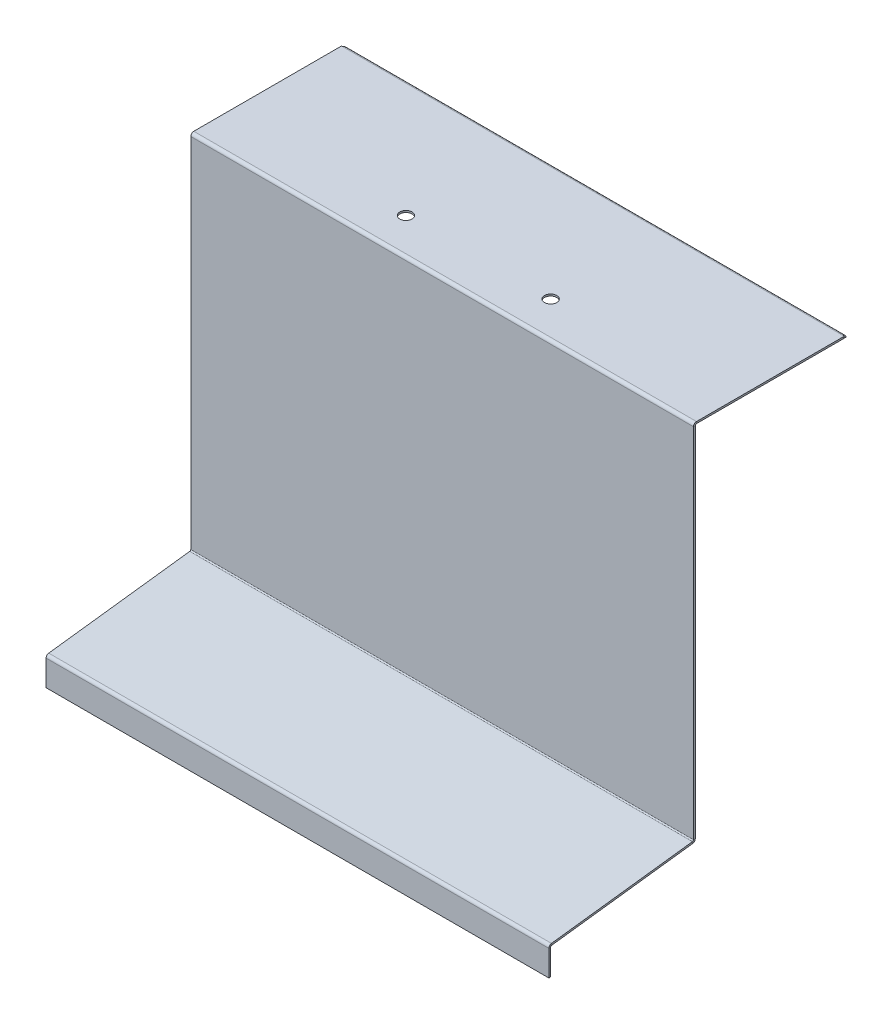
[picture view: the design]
ISO-10303-21;
HEADER;
FILE_DESCRIPTION(('STEP AP214'),'2;1');
FILE_NAME('part.step','',(''),(''),'','','');
FILE_SCHEMA(('AUTOMOTIVE_DESIGN { 1 0 10303 214 1 1 1 1 }'));
ENDSEC;
DATA;
#1=APPLICATION_CONTEXT('core data for automotive mechanical design processes');
#2=APPLICATION_PROTOCOL_DEFINITION('international standard','automotive_design',2000,#1);
#3=PRODUCT_CONTEXT('',#1,'mechanical');
#4=PRODUCT('Part','Part','',(#3));
#5=PRODUCT_RELATED_PRODUCT_CATEGORY('part','',(#4));
#6=PRODUCT_DEFINITION_FORMATION('','',#4);
#7=PRODUCT_DEFINITION_CONTEXT('part definition',#1,'design');
#8=PRODUCT_DEFINITION('design','',#6,#7);
#9=PRODUCT_DEFINITION_SHAPE('','',#8);
#10=(LENGTH_UNIT() NAMED_UNIT(*) SI_UNIT(.MILLI.,.METRE.));
#11=(NAMED_UNIT(*) PLANE_ANGLE_UNIT() SI_UNIT($,.RADIAN.));
#12=(NAMED_UNIT(*) SI_UNIT($,.STERADIAN.) SOLID_ANGLE_UNIT());
#13=UNCERTAINTY_MEASURE_WITH_UNIT(LENGTH_MEASURE(1.E-05),#10,'distance_accuracy_value','');
#14=(GEOMETRIC_REPRESENTATION_CONTEXT(3) GLOBAL_UNCERTAINTY_ASSIGNED_CONTEXT((#13)) GLOBAL_UNIT_ASSIGNED_CONTEXT((#10,
#11,#12)) REPRESENTATION_CONTEXT('',''));
#15=CARTESIAN_POINT('',(0.,0.,0.));
#16=DIRECTION('',(0.,0.,1.));
#17=DIRECTION('',(1.,0.,0.));
#18=AXIS2_PLACEMENT_3D('',#15,#16,#17);
#19=CARTESIAN_POINT('',(0.,338.5,-125.));
#20=DIRECTION('',(0.,-1.,0.));
#21=DIRECTION('',(0.,0.,-1.));
#22=AXIS2_PLACEMENT_3D('',#19,#20,#21);
#23=PLANE('',#22);
#24=CARTESIAN_POINT('',(148.5,338.5,-30.));
#25=DIRECTION('',(0.,-1.,0.));
#26=DIRECTION('',(0.,0.,-1.));
#27=AXIS2_PLACEMENT_3D('',#24,#25,#26);
#28=CIRCLE('',#27,5.09999999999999);
#29=CARTESIAN_POINT('',(148.5,338.5,-35.1));
#30=VERTEX_POINT('',#29);
#31=EDGE_CURVE('E643',#30,#30,#28,.T.);
#32=ORIENTED_EDGE('',*,*,#31,.F.);
#33=EDGE_LOOP('',(#32));
#34=FACE_BOUND('',#33,.T.);
#35=CARTESIAN_POINT('',(268.5,338.5,-30.));
#36=DIRECTION('',(0.,-1.,0.));
#37=DIRECTION('',(0.,0.,-1.));
#38=AXIS2_PLACEMENT_3D('',#35,#36,#37);
#39=CIRCLE('',#38,5.09999999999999);
#40=CARTESIAN_POINT('',(268.5,338.5,-35.1));
#41=VERTEX_POINT('',#40);
#42=EDGE_CURVE('E637',#41,#41,#39,.T.);
#43=ORIENTED_EDGE('',*,*,#42,.F.);
#44=EDGE_LOOP('',(#43));
#45=FACE_BOUND('',#44,.T.);
#46=DIRECTION('',(1.,0.,0.));
#47=VECTOR('',#46,1.);
#48=CARTESIAN_POINT('',(0.,338.5,-125.));
#49=LINE('',#48,#47);
#50=CARTESIAN_POINT('',(1.07071068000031,338.5,-124.9999999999));
#51=VERTEX_POINT('',#50);
#52=CARTESIAN_POINT('',(0.,338.5,-125.));
#53=VERTEX_POINT('',#52);
#54=EDGE_CURVE('E73',#51,#53,#49,.F.);
#55=ORIENTED_EDGE('',*,*,#54,.F.);
#56=DIRECTION('',(1.,0.,0.));
#57=VECTOR('',#56,1.);
#58=CARTESIAN_POINT('',(0.,338.5,-124.999999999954));
#59=LINE('',#58,#57);
#60=CARTESIAN_POINT('',(415.9292893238,338.5,-124.9999999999));
#61=VERTEX_POINT('',#60);
#62=EDGE_CURVE('E57',#51,#61,#59,.T.);
#63=ORIENTED_EDGE('',*,*,#62,.T.);
#64=CARTESIAN_POINT('',(417.,338.5,-125.));
#65=VERTEX_POINT('',#64);
#66=EDGE_CURVE('E409',#65,#61,#49,.F.);
#67=ORIENTED_EDGE('',*,*,#66,.F.);
#68=DIRECTION('',(0.,0.,-1.));
#69=VECTOR('',#68,1.);
#70=CARTESIAN_POINT('',(417.,338.5,-125.));
#71=LINE('',#70,#69);
#72=CARTESIAN_POINT('',(417.,338.5,-2.5));
#73=VERTEX_POINT('',#72);
#74=EDGE_CURVE('E402',#73,#65,#71,.T.);
#75=ORIENTED_EDGE('',*,*,#74,.F.);
#76=DIRECTION('',(1.,0.,0.));
#77=VECTOR('',#76,1.);
#78=CARTESIAN_POINT('',(0.,338.5,-2.5));
#79=LINE('',#78,#77);
#80=CARTESIAN_POINT('',(0.,338.5,-2.5));
#81=VERTEX_POINT('',#80);
#82=EDGE_CURVE('E376',#81,#73,#79,.T.);
#83=ORIENTED_EDGE('',*,*,#82,.F.);
#84=DIRECTION('',(0.,0.,-1.));
#85=VECTOR('',#84,1.);
#86=CARTESIAN_POINT('',(0.,338.5,-125.));
#87=LINE('',#86,#85);
#88=EDGE_CURVE('E407',#53,#81,#87,.F.);
#89=ORIENTED_EDGE('',*,*,#88,.F.);
#90=EDGE_LOOP('',(#55,#63,#67,#75,#83,#89));
#91=FACE_BOUND('',#90,.T.);
#92=ADVANCED_FACE('F49',(#34,#45,#91),#23,.T.);
#93=CARTESIAN_POINT('',(0.,340.,-125.));
#94=DIRECTION('',(0.,-1.,0.));
#95=DIRECTION('',(0.,0.,-1.));
#96=AXIS2_PLACEMENT_3D('',#93,#94,#95);
#97=PLANE('',#96);
#98=CARTESIAN_POINT('',(148.5,340.,-30.));
#99=DIRECTION('',(0.,1.,0.));
#100=DIRECTION('',(0.,0.,1.));
#101=AXIS2_PLACEMENT_3D('',#98,#99,#100);
#102=CIRCLE('',#101,5.09999999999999);
#103=CARTESIAN_POINT('',(148.5,340.,-24.9));
#104=VERTEX_POINT('',#103);
#105=EDGE_CURVE('E646',#104,#104,#102,.T.);
#106=ORIENTED_EDGE('',*,*,#105,.F.);
#107=EDGE_LOOP('',(#106));
#108=FACE_BOUND('',#107,.T.);
#109=CARTESIAN_POINT('',(268.5,340.,-30.));
#110=DIRECTION('',(0.,1.,0.));
#111=DIRECTION('',(0.,0.,1.));
#112=AXIS2_PLACEMENT_3D('',#109,#110,#111);
#113=CIRCLE('',#112,5.09999999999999);
#114=CARTESIAN_POINT('',(268.5,340.,-24.9));
#115=VERTEX_POINT('',#114);
#116=EDGE_CURVE('E640',#115,#115,#113,.T.);
#117=ORIENTED_EDGE('',*,*,#116,.F.);
#118=EDGE_LOOP('',(#117));
#119=FACE_BOUND('',#118,.T.);
#120=DIRECTION('',(1.,0.,0.));
#121=VECTOR('',#120,1.);
#122=CARTESIAN_POINT('',(0.,340.,-124.999999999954));
#123=LINE('',#122,#121);
#124=CARTESIAN_POINT('',(1.07071068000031,340.,-124.9999999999));
#125=VERTEX_POINT('',#124);
#126=CARTESIAN_POINT('',(415.9292893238,340.,-125.));
#127=VERTEX_POINT('',#126);
#128=EDGE_CURVE('E457',#125,#127,#123,.T.);
#129=ORIENTED_EDGE('',*,*,#128,.F.);
#130=DIRECTION('',(-1.,0.,0.));
#131=VECTOR('',#130,1.);
#132=CARTESIAN_POINT('',(0.,340.,-125.));
#133=LINE('',#132,#131);
#134=CARTESIAN_POINT('',(0.,340.,-125.));
#135=VERTEX_POINT('',#134);
#136=EDGE_CURVE('E385',#125,#135,#133,.T.);
#137=ORIENTED_EDGE('',*,*,#136,.T.);
#138=DIRECTION('',(0.,0.,1.));
#139=VECTOR('',#138,1.);
#140=CARTESIAN_POINT('',(0.,340.,0.));
#141=LINE('',#140,#139);
#142=CARTESIAN_POINT('',(0.,340.,-2.49999999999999));
#143=VERTEX_POINT('',#142);
#144=EDGE_CURVE('E397',#135,#143,#141,.T.);
#145=ORIENTED_EDGE('',*,*,#144,.T.);
#146=DIRECTION('',(1.,0.,0.));
#147=VECTOR('',#146,1.);
#148=CARTESIAN_POINT('',(0.,340.,-2.5));
#149=LINE('',#148,#147);
#150=CARTESIAN_POINT('',(417.,340.,-2.5));
#151=VERTEX_POINT('',#150);
#152=EDGE_CURVE('E395',#143,#151,#149,.T.);
#153=ORIENTED_EDGE('',*,*,#152,.T.);
#154=DIRECTION('',(0.,0.,-1.));
#155=VECTOR('',#154,1.);
#156=CARTESIAN_POINT('',(417.,340.,0.));
#157=LINE('',#156,#155);
#158=CARTESIAN_POINT('',(417.,340.,-125.));
#159=VERTEX_POINT('',#158);
#160=EDGE_CURVE('E392',#151,#159,#157,.T.);
#161=ORIENTED_EDGE('',*,*,#160,.T.);
#162=EDGE_CURVE('E387',#159,#127,#133,.T.);
#163=ORIENTED_EDGE('',*,*,#162,.T.);
#164=EDGE_LOOP('',(#129,#137,#145,#153,#161,#163));
#165=FACE_BOUND('',#164,.T.);
#166=ADVANCED_FACE('F652',(#108,#119,#165),#97,.F.);
#167=CARTESIAN_POINT('',(417.,40.,0.));
#168=DIRECTION('',(-1.,0.,0.));
#169=DIRECTION('',(0.,-0.124034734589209,0.992277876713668));
#170=AXIS2_PLACEMENT_3D('',#167,#168,#169);
#171=PLANE('',#170);
#172=DIRECTION('',(0.,0.992277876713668,0.124034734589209));
#173=VECTOR('',#172,1.);
#174=CARTESIAN_POINT('',(417.,25.2737391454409,117.810086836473));
#175=LINE('',#174,#173);
#176=CARTESIAN_POINT('',(417.,23.7853223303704,117.624034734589));
#177=VERTEX_POINT('',#176);
#178=CARTESIAN_POINT('',(417.,25.2737391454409,117.810086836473));
#179=VERTEX_POINT('',#178);
#180=EDGE_CURVE('E454',#177,#179,#175,.T.);
#181=ORIENTED_EDGE('',*,*,#180,.F.);
#182=DIRECTION('',(0.,-0.124034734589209,0.992277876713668));
#183=VECTOR('',#182,1.);
#184=CARTESIAN_POINT('',(417.,38.5115831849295,-0.186052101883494));
#185=LINE('',#184,#183);
#186=CARTESIAN_POINT('',(417.,38.4020875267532,0.689913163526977));
#187=VERTEX_POINT('',#186);
#188=EDGE_CURVE('E430',#187,#177,#185,.T.);
#189=ORIENTED_EDGE('',*,*,#188,.F.);
#190=DIRECTION('',(-1.11022302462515E-13,0.992277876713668,0.124034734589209));
#191=VECTOR('',#190,1.);
#192=CARTESIAN_POINT('',(417.,39.8905043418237,0.875965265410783));
#193=LINE('',#192,#191);
#194=CARTESIAN_POINT('',(417.,39.8905043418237,0.87596526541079));
#195=VERTEX_POINT('',#194);
#196=EDGE_CURVE('E436',#187,#195,#193,.T.);
#197=ORIENTED_EDGE('',*,*,#196,.T.);
#198=DIRECTION('',(0.,-0.124034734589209,0.992277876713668));
#199=VECTOR('',#198,1.);
#200=CARTESIAN_POINT('',(417.,40.,0.));
#201=LINE('',#200,#199);
#202=EDGE_CURVE('E429',#195,#179,#201,.T.);
#203=ORIENTED_EDGE('',*,*,#202,.T.);
#204=EDGE_LOOP('',(#181,#189,#197,#203));
#205=FACE_BOUND('',#204,.T.);
#206=ADVANCED_FACE('F655',(#205),#171,.F.);
#207=CARTESIAN_POINT('',(0.,40.,3.33066907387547E-13));
#208=DIRECTION('',(1.,0.,0.));
#209=DIRECTION('',(0.,0.124034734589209,-0.992277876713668));
#210=AXIS2_PLACEMENT_3D('',#207,#208,#209);
#211=PLANE('',#210);
#212=DIRECTION('',(0.,0.992277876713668,0.124034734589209));
#213=VECTOR('',#212,1.);
#214=CARTESIAN_POINT('',(0.,39.8905043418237,0.87596526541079));
#215=LINE('',#214,#213);
#216=CARTESIAN_POINT('',(0.,38.4020875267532,0.689913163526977));
#217=VERTEX_POINT('',#216);
#218=CARTESIAN_POINT('',(0.,39.8905043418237,0.875965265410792));
#219=VERTEX_POINT('',#218);
#220=EDGE_CURVE('E442',#217,#219,#215,.T.);
#221=ORIENTED_EDGE('',*,*,#220,.F.);
#222=DIRECTION('',(0.,-0.124034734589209,0.992277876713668));
#223=VECTOR('',#222,1.);
#224=CARTESIAN_POINT('',(0.,38.5115831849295,-0.18605210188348));
#225=LINE('',#224,#223);
#226=CARTESIAN_POINT('',(0.,23.7853223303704,117.624034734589));
#227=VERTEX_POINT('',#226);
#228=EDGE_CURVE('E339',#227,#217,#225,.F.);
#229=ORIENTED_EDGE('',*,*,#228,.F.);
#230=DIRECTION('',(0.,0.992277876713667,0.12403473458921));
#231=VECTOR('',#230,1.);
#232=CARTESIAN_POINT('',(0.,25.2737391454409,117.810086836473));
#233=LINE('',#232,#231);
#234=CARTESIAN_POINT('',(0.,25.2737391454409,117.810086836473));
#235=VERTEX_POINT('',#234);
#236=EDGE_CURVE('E448',#227,#235,#233,.T.);
#237=ORIENTED_EDGE('',*,*,#236,.T.);
#238=DIRECTION('',(0.,0.124034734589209,-0.992277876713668));
#239=VECTOR('',#238,1.);
#240=CARTESIAN_POINT('',(0.,40.,3.33066907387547E-13));
#241=LINE('',#240,#239);
#242=EDGE_CURVE('E426',#235,#219,#241,.T.);
#243=ORIENTED_EDGE('',*,*,#242,.T.);
#244=EDGE_LOOP('',(#221,#229,#237,#243));
#245=FACE_BOUND('',#244,.T.);
#246=ADVANCED_FACE('F903',(#245),#211,.F.);
#247=CARTESIAN_POINT('',(-126.491106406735,40.,3.33066907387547E-13));
#248=DIRECTION('',(0.,0.992277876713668,0.124034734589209));
#249=DIRECTION('',(0.,-0.124034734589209,0.992277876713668));
#250=AXIS2_PLACEMENT_3D('',#247,#248,#249);
#251=PLANE('',#250);
#252=ORIENTED_EDGE('',*,*,#202,.F.);
#253=DIRECTION('',(-1.,0.,0.));
#254=VECTOR('',#253,1.);
#255=CARTESIAN_POINT('',(-126.491106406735,39.8905043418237,0.875965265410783));
#256=LINE('',#255,#254);
#257=EDGE_CURVE('E432',#195,#219,#256,.T.);
#258=ORIENTED_EDGE('',*,*,#257,.T.);
#259=ORIENTED_EDGE('',*,*,#242,.F.);
#260=DIRECTION('',(1.,0.,0.));
#261=VECTOR('',#260,1.);
#262=CARTESIAN_POINT('',(-126.491106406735,25.2737391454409,117.810086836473));
#263=LINE('',#262,#261);
#264=EDGE_CURVE('E445',#235,#179,#263,.T.);
#265=ORIENTED_EDGE('',*,*,#264,.T.);
#266=EDGE_LOOP('',(#252,#258,#259,#265));
#267=FACE_BOUND('',#266,.T.);
#268=ADVANCED_FACE('F897',(#267),#251,.T.);
#269=CARTESIAN_POINT('',(-126.491106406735,38.5115831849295,-0.18605210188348));
#270=DIRECTION('',(0.,0.992277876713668,0.124034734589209));
#271=DIRECTION('',(0.,-0.124034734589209,0.992277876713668));
#272=AXIS2_PLACEMENT_3D('',#269,#270,#271);
#273=PLANE('',#272);
#274=ORIENTED_EDGE('',*,*,#188,.T.);
#275=DIRECTION('',(1.,0.,0.));
#276=VECTOR('',#275,1.);
#277=CARTESIAN_POINT('',(-126.491106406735,23.7853223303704,117.624034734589));
#278=LINE('',#277,#276);
#279=EDGE_CURVE('E451',#227,#177,#278,.T.);
#280=ORIENTED_EDGE('',*,*,#279,.F.);
#281=ORIENTED_EDGE('',*,*,#228,.T.);
#282=DIRECTION('',(-1.,0.,0.));
#283=VECTOR('',#282,1.);
#284=CARTESIAN_POINT('',(-126.491106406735,38.4020875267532,0.689913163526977));
#285=LINE('',#284,#283);
#286=EDGE_CURVE('E439',#187,#217,#285,.T.);
#287=ORIENTED_EDGE('',*,*,#286,.F.);
#288=EDGE_LOOP('',(#274,#280,#281,#287));
#289=FACE_BOUND('',#288,.T.);
#290=ADVANCED_FACE('F893',(#289),#273,.F.);
#291=CARTESIAN_POINT('',(0.,340.,-125.));
#292=DIRECTION('',(0.,0.,1.));
#293=DIRECTION('',(-1.,0.,0.));
#294=AXIS2_PLACEMENT_3D('',#291,#292,#293);
#295=PLANE('',#294);
#296=DIRECTION('',(0.,1.,0.));
#297=VECTOR('',#296,1.);
#298=CARTESIAN_POINT('',(1.07071068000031,338.5,-124.9999999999));
#299=LINE('',#298,#297);
#300=EDGE_CURVE('E12',#51,#125,#299,.T.);
#301=ORIENTED_EDGE('',*,*,#300,.F.);
#302=ORIENTED_EDGE('',*,*,#54,.T.);
#303=DIRECTION('',(0.,1.,0.));
#304=VECTOR('',#303,1.);
#305=CARTESIAN_POINT('',(0.,340.,-125.));
#306=LINE('',#305,#304);
#307=EDGE_CURVE('E411',#53,#135,#306,.T.);
#308=ORIENTED_EDGE('',*,*,#307,.T.);
#309=ORIENTED_EDGE('',*,*,#136,.F.);
#310=EDGE_LOOP('',(#301,#302,#308,#309));
#311=FACE_BOUND('',#310,.T.);
#312=ADVANCED_FACE('F668',(#311),#295,.F.);
#313=ORIENTED_EDGE('',*,*,#66,.T.);
#314=DIRECTION('',(0.,1.,0.));
#315=VECTOR('',#314,1.);
#316=CARTESIAN_POINT('',(415.9292893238,338.5,-124.9999999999));
#317=LINE('',#316,#315);
#318=EDGE_CURVE('E460',#61,#127,#317,.T.);
#319=ORIENTED_EDGE('',*,*,#318,.T.);
#320=ORIENTED_EDGE('',*,*,#162,.F.);
#321=DIRECTION('',(0.,1.,0.));
#322=VECTOR('',#321,1.);
#323=CARTESIAN_POINT('',(417.,340.,-125.));
#324=LINE('',#323,#322);
#325=EDGE_CURVE('E400',#65,#159,#324,.T.);
#326=ORIENTED_EDGE('',*,*,#325,.F.);
#327=EDGE_LOOP('',(#313,#319,#320,#326));
#328=FACE_BOUND('',#327,.T.);
#329=ADVANCED_FACE('F675',(#328),#295,.F.);
#330=CARTESIAN_POINT('',(0.,340.,0.));
#331=DIRECTION('',(1.,0.,0.));
#332=DIRECTION('',(0.,0.,1.));
#333=AXIS2_PLACEMENT_3D('',#330,#331,#332);
#334=PLANE('',#333);
#335=ORIENTED_EDGE('',*,*,#307,.F.);
#336=ORIENTED_EDGE('',*,*,#88,.T.);
#337=DIRECTION('',(0.,1.,0.));
#338=VECTOR('',#337,1.);
#339=CARTESIAN_POINT('',(0.,340.,-2.5));
#340=LINE('',#339,#338);
#341=EDGE_CURVE('E405',#81,#143,#340,.T.);
#342=ORIENTED_EDGE('',*,*,#341,.T.);
#343=ORIENTED_EDGE('',*,*,#144,.F.);
#344=EDGE_LOOP('',(#335,#336,#342,#343));
#345=FACE_BOUND('',#344,.T.);
#346=ADVANCED_FACE('F711',(#345),#334,.F.);
#347=CARTESIAN_POINT('',(417.,340.,0.));
#348=DIRECTION('',(-1.,0.,0.));
#349=DIRECTION('',(0.,0.,-1.));
#350=AXIS2_PLACEMENT_3D('',#347,#348,#349);
#351=PLANE('',#350);
#352=DIRECTION('',(0.,1.,0.));
#353=VECTOR('',#352,1.);
#354=CARTESIAN_POINT('',(417.,340.,-2.5));
#355=LINE('',#354,#353);
#356=EDGE_CURVE('E367',#73,#151,#355,.T.);
#357=ORIENTED_EDGE('',*,*,#356,.F.);
#358=ORIENTED_EDGE('',*,*,#74,.T.);
#359=ORIENTED_EDGE('',*,*,#325,.T.);
#360=ORIENTED_EDGE('',*,*,#160,.F.);
#361=EDGE_LOOP('',(#357,#358,#359,#360));
#362=FACE_BOUND('',#361,.T.);
#363=ADVANCED_FACE('F679',(#362),#351,.F.);
#364=CARTESIAN_POINT('',(0.,337.5,-2.5));
#365=DIRECTION('',(-1.,0.,0.));
#366=DIRECTION('',(0.,0.,1.));
#367=AXIS2_PLACEMENT_3D('',#364,#365,#366);
#368=PLANE('',#367);
#369=ORIENTED_EDGE('',*,*,#341,.F.);
#370=CARTESIAN_POINT('',(0.,337.5,-2.5));
#371=DIRECTION('',(-1.,0.,0.));
#372=DIRECTION('',(0.,0.,1.));
#373=AXIS2_PLACEMENT_3D('',#370,#371,#372);
#374=CIRCLE('',#373,1.);
#375=CARTESIAN_POINT('',(0.,337.5,-1.5));
#376=VERTEX_POINT('',#375);
#377=EDGE_CURVE('E382',#81,#376,#374,.F.);
#378=ORIENTED_EDGE('',*,*,#377,.T.);
#379=DIRECTION('',(0.,0.,1.));
#380=VECTOR('',#379,1.);
#381=CARTESIAN_POINT('',(0.,337.5,0.));
#382=LINE('',#381,#380);
#383=CARTESIAN_POINT('',(0.,337.5,0.));
#384=VERTEX_POINT('',#383);
#385=EDGE_CURVE('E379',#376,#384,#382,.T.);
#386=ORIENTED_EDGE('',*,*,#385,.T.);
#387=CARTESIAN_POINT('',(0.,337.5,-2.5));
#388=DIRECTION('',(1.,0.,0.));
#389=DIRECTION('',(0.,0.,-1.));
#390=AXIS2_PLACEMENT_3D('',#387,#388,#389);
#391=CIRCLE('',#390,2.5);
#392=EDGE_CURVE('E364',#143,#384,#391,.T.);
#393=ORIENTED_EDGE('',*,*,#392,.F.);
#394=EDGE_LOOP('',(#369,#378,#386,#393));
#395=FACE_BOUND('',#394,.T.);
#396=ADVANCED_FACE('F689',(#395),#368,.T.);
#397=CARTESIAN_POINT('',(625.511758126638,337.5,-2.5));
#398=DIRECTION('',(-1.,0.,0.));
#399=DIRECTION('',(0.,0.,1.));
#400=AXIS2_PLACEMENT_3D('',#397,#398,#399);
#401=CYLINDRICAL_SURFACE('',#400,1.);
#402=ORIENTED_EDGE('',*,*,#377,.F.);
#403=ORIENTED_EDGE('',*,*,#82,.T.);
#404=CARTESIAN_POINT('',(417.,337.5,-2.5));
#405=DIRECTION('',(-1.,0.,0.));
#406=DIRECTION('',(0.,0.,1.));
#407=AXIS2_PLACEMENT_3D('',#404,#405,#406);
#408=CIRCLE('',#407,1.);
#409=CARTESIAN_POINT('',(417.,337.5,-1.5));
#410=VERTEX_POINT('',#409);
#411=EDGE_CURVE('E370',#410,#73,#408,.T.);
#412=ORIENTED_EDGE('',*,*,#411,.F.);
#413=DIRECTION('',(-1.,0.,0.));
#414=VECTOR('',#413,1.);
#415=CARTESIAN_POINT('',(0.,337.5,-1.5));
#416=LINE('',#415,#414);
#417=EDGE_CURVE('E373',#410,#376,#416,.T.);
#418=ORIENTED_EDGE('',*,*,#417,.T.);
#419=EDGE_LOOP('',(#402,#403,#412,#418));
#420=FACE_BOUND('',#419,.T.);
#421=ADVANCED_FACE('F709',(#420),#401,.F.);
#422=CARTESIAN_POINT('',(417.,337.5,-2.5));
#423=DIRECTION('',(1.,0.,0.));
#424=DIRECTION('',(0.,0.,-1.));
#425=AXIS2_PLACEMENT_3D('',#422,#423,#424);
#426=PLANE('',#425);
#427=DIRECTION('',(0.,0.,1.));
#428=VECTOR('',#427,1.);
#429=CARTESIAN_POINT('',(417.,337.5,0.));
#430=LINE('',#429,#428);
#431=CARTESIAN_POINT('',(417.,337.5,0.));
#432=VERTEX_POINT('',#431);
#433=EDGE_CURVE('E346',#410,#432,#430,.T.);
#434=ORIENTED_EDGE('',*,*,#433,.F.);
#435=ORIENTED_EDGE('',*,*,#411,.T.);
#436=ORIENTED_EDGE('',*,*,#356,.T.);
#437=CARTESIAN_POINT('',(417.,337.5,-2.5));
#438=DIRECTION('',(-1.,0.,0.));
#439=DIRECTION('',(0.,0.,1.));
#440=AXIS2_PLACEMENT_3D('',#437,#438,#439);
#441=CIRCLE('',#440,2.5);
#442=EDGE_CURVE('E361',#432,#151,#441,.T.);
#443=ORIENTED_EDGE('',*,*,#442,.F.);
#444=EDGE_LOOP('',(#434,#435,#436,#443));
#445=FACE_BOUND('',#444,.T.);
#446=ADVANCED_FACE('F706',(#445),#426,.T.);
#447=CARTESIAN_POINT('',(625.511758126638,337.5,-2.5));
#448=DIRECTION('',(-1.,0.,0.));
#449=DIRECTION('',(0.,0.,1.));
#450=AXIS2_PLACEMENT_3D('',#447,#448,#449);
#451=CYLINDRICAL_SURFACE('',#450,2.5);
#452=ORIENTED_EDGE('',*,*,#392,.T.);
#453=DIRECTION('',(-1.,0.,0.));
#454=VECTOR('',#453,1.);
#455=CARTESIAN_POINT('',(0.,337.5,0.));
#456=LINE('',#455,#454);
#457=EDGE_CURVE('E356',#432,#384,#456,.T.);
#458=ORIENTED_EDGE('',*,*,#457,.F.);
#459=ORIENTED_EDGE('',*,*,#442,.T.);
#460=ORIENTED_EDGE('',*,*,#152,.F.);
#461=EDGE_LOOP('',(#452,#458,#459,#460));
#462=FACE_BOUND('',#461,.T.);
#463=ADVANCED_FACE('F684',(#462),#451,.T.);
#464=CARTESIAN_POINT('',(0.,340.,0.));
#465=DIRECTION('',(0.,0.,-1.));
#466=DIRECTION('',(-1.,0.,0.));
#467=AXIS2_PLACEMENT_3D('',#464,#465,#466);
#468=PLANE('',#467);
#469=DIRECTION('',(0.,-1.,0.));
#470=VECTOR('',#469,1.);
#471=CARTESIAN_POINT('',(417.,340.,0.));
#472=LINE('',#471,#470);
#473=CARTESIAN_POINT('',(417.,40.8827822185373,0.));
#474=VERTEX_POINT('',#473);
#475=EDGE_CURVE('E344',#432,#474,#472,.T.);
#476=ORIENTED_EDGE('',*,*,#475,.F.);
#477=ORIENTED_EDGE('',*,*,#457,.T.);
#478=DIRECTION('',(0.,-1.,0.));
#479=VECTOR('',#478,1.);
#480=CARTESIAN_POINT('',(0.,340.,0.));
#481=LINE('',#480,#479);
#482=CARTESIAN_POINT('',(0.,40.8827822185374,0.));
#483=VERTEX_POINT('',#482);
#484=EDGE_CURVE('E354',#384,#483,#481,.T.);
#485=ORIENTED_EDGE('',*,*,#484,.T.);
#486=DIRECTION('',(1.,0.,0.));
#487=VECTOR('',#486,1.);
#488=CARTESIAN_POINT('',(0.,40.8827822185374,0.));
#489=LINE('',#488,#487);
#490=EDGE_CURVE('E351',#483,#474,#489,.T.);
#491=ORIENTED_EDGE('',*,*,#490,.T.);
#492=EDGE_LOOP('',(#476,#477,#485,#491));
#493=FACE_BOUND('',#492,.T.);
#494=ADVANCED_FACE('F698',(#493),#468,.F.);
#495=CARTESIAN_POINT('',(417.,340.,0.));
#496=DIRECTION('',(1.,0.,0.));
#497=DIRECTION('',(0.,-1.,0.));
#498=AXIS2_PLACEMENT_3D('',#495,#496,#497);
#499=PLANE('',#498);
#500=DIRECTION('',(0.,0.,1.));
#501=VECTOR('',#500,1.);
#502=CARTESIAN_POINT('',(417.,40.8827822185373,0.));
#503=LINE('',#502,#501);
#504=CARTESIAN_POINT('',(417.,40.8827822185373,-1.5));
#505=VERTEX_POINT('',#504);
#506=EDGE_CURVE('E417',#505,#474,#503,.T.);
#507=ORIENTED_EDGE('',*,*,#506,.F.);
#508=DIRECTION('',(0.,1.,0.));
#509=VECTOR('',#508,1.);
#510=CARTESIAN_POINT('',(417.,340.,-1.5));
#511=LINE('',#510,#509);
#512=EDGE_CURVE('E342',#410,#505,#511,.F.);
#513=ORIENTED_EDGE('',*,*,#512,.F.);
#514=ORIENTED_EDGE('',*,*,#433,.T.);
#515=ORIENTED_EDGE('',*,*,#475,.T.);
#516=EDGE_LOOP('',(#507,#513,#514,#515));
#517=FACE_BOUND('',#516,.T.);
#518=ADVANCED_FACE('F702',(#517),#499,.T.);
#519=CARTESIAN_POINT('',(0.,340.,-1.5));
#520=DIRECTION('',(0.,0.,-1.));
#521=DIRECTION('',(-1.,0.,0.));
#522=AXIS2_PLACEMENT_3D('',#519,#520,#521);
#523=PLANE('',#522);
#524=ORIENTED_EDGE('',*,*,#512,.T.);
#525=DIRECTION('',(1.,0.,0.));
#526=VECTOR('',#525,1.);
#527=CARTESIAN_POINT('',(0.,40.8827822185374,-1.5));
#528=LINE('',#527,#526);
#529=CARTESIAN_POINT('',(0.,40.8827822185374,-1.5));
#530=VERTEX_POINT('',#529);
#531=EDGE_CURVE('E331',#530,#505,#528,.T.);
#532=ORIENTED_EDGE('',*,*,#531,.F.);
#533=DIRECTION('',(0.,1.,0.));
#534=VECTOR('',#533,1.);
#535=CARTESIAN_POINT('',(0.,340.,-1.5));
#536=LINE('',#535,#534);
#537=EDGE_CURVE('E340',#376,#530,#536,.F.);
#538=ORIENTED_EDGE('',*,*,#537,.F.);
#539=ORIENTED_EDGE('',*,*,#417,.F.);
#540=EDGE_LOOP('',(#524,#532,#538,#539));
#541=FACE_BOUND('',#540,.T.);
#542=ADVANCED_FACE('F935',(#541),#523,.T.);
#543=CARTESIAN_POINT('',(0.,340.,0.));
#544=DIRECTION('',(1.,0.,0.));
#545=DIRECTION('',(0.,-1.,0.));
#546=AXIS2_PLACEMENT_3D('',#543,#544,#545);
#547=PLANE('',#546);
#548=ORIENTED_EDGE('',*,*,#385,.F.);
#549=ORIENTED_EDGE('',*,*,#537,.T.);
#550=DIRECTION('',(0.,0.,1.));
#551=VECTOR('',#550,1.);
#552=CARTESIAN_POINT('',(0.,40.8827822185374,0.));
#553=LINE('',#552,#551);
#554=EDGE_CURVE('E336',#530,#483,#553,.T.);
#555=ORIENTED_EDGE('',*,*,#554,.T.);
#556=ORIENTED_EDGE('',*,*,#484,.F.);
#557=EDGE_LOOP('',(#548,#549,#555,#556));
#558=FACE_BOUND('',#557,.T.);
#559=ADVANCED_FACE('F693',(#558),#547,.F.);
#560=CARTESIAN_POINT('',(417.,40.8827822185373,1.));
#561=DIRECTION('',(-1.,0.,0.));
#562=DIRECTION('',(0.,0.,1.));
#563=AXIS2_PLACEMENT_3D('',#560,#561,#562);
#564=PLANE('',#563);
#565=ORIENTED_EDGE('',*,*,#196,.F.);
#566=CARTESIAN_POINT('',(417.,40.8827822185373,1.));
#567=DIRECTION('',(1.,0.,0.));
#568=DIRECTION('',(0.,1.,0.));
#569=AXIS2_PLACEMENT_3D('',#566,#567,#568);
#570=CIRCLE('',#569,2.5);
#571=EDGE_CURVE('E321',#187,#505,#570,.T.);
#572=ORIENTED_EDGE('',*,*,#571,.T.);
#573=ORIENTED_EDGE('',*,*,#506,.T.);
#574=CARTESIAN_POINT('',(417.,40.8827822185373,1.));
#575=DIRECTION('',(1.,0.,0.));
#576=DIRECTION('',(0.,0.,-1.));
#577=AXIS2_PLACEMENT_3D('',#574,#575,#576);
#578=CIRCLE('',#577,1.);
#579=EDGE_CURVE('E324',#195,#474,#578,.T.);
#580=ORIENTED_EDGE('',*,*,#579,.F.);
#581=EDGE_LOOP('',(#565,#572,#573,#580));
#582=FACE_BOUND('',#581,.T.);
#583=ADVANCED_FACE('F888',(#582),#564,.F.);
#584=CARTESIAN_POINT('',(0.,40.8827822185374,1.));
#585=DIRECTION('',(1.,0.,0.));
#586=DIRECTION('',(0.,1.,0.));
#587=AXIS2_PLACEMENT_3D('',#584,#585,#586);
#588=PLANE('',#587);
#589=ORIENTED_EDGE('',*,*,#554,.F.);
#590=CARTESIAN_POINT('',(0.,40.8827822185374,1.));
#591=DIRECTION('',(1.,0.,0.));
#592=DIRECTION('',(0.,1.,0.));
#593=AXIS2_PLACEMENT_3D('',#590,#591,#592);
#594=CIRCLE('',#593,2.5);
#595=EDGE_CURVE('E328',#530,#217,#594,.F.);
#596=ORIENTED_EDGE('',*,*,#595,.T.);
#597=ORIENTED_EDGE('',*,*,#220,.T.);
#598=CARTESIAN_POINT('',(0.,40.8827822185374,1.));
#599=DIRECTION('',(-1.,0.,0.));
#600=DIRECTION('',(0.,-1.,0.));
#601=AXIS2_PLACEMENT_3D('',#598,#599,#600);
#602=CIRCLE('',#601,0.999999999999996);
#603=EDGE_CURVE('E327',#483,#219,#602,.T.);
#604=ORIENTED_EDGE('',*,*,#603,.F.);
#605=EDGE_LOOP('',(#589,#596,#597,#604));
#606=FACE_BOUND('',#605,.T.);
#607=ADVANCED_FACE('F881',(#606),#588,.F.);
#608=CARTESIAN_POINT('',(-208.510380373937,40.8827822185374,1.));
#609=DIRECTION('',(1.,0.,0.));
#610=DIRECTION('',(0.,1.,0.));
#611=AXIS2_PLACEMENT_3D('',#608,#609,#610);
#612=CYLINDRICAL_SURFACE('',#611,1.);
#613=ORIENTED_EDGE('',*,*,#603,.T.);
#614=ORIENTED_EDGE('',*,*,#257,.F.);
#615=ORIENTED_EDGE('',*,*,#579,.T.);
#616=ORIENTED_EDGE('',*,*,#490,.F.);
#617=EDGE_LOOP('',(#613,#614,#615,#616));
#618=FACE_BOUND('',#617,.T.);
#619=ADVANCED_FACE('F878',(#618),#612,.F.);
#620=CARTESIAN_POINT('',(-208.510380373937,40.8827822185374,1.));
#621=DIRECTION('',(1.,0.,0.));
#622=DIRECTION('',(0.,1.,0.));
#623=AXIS2_PLACEMENT_3D('',#620,#621,#622);
#624=CYLINDRICAL_SURFACE('',#623,2.5);
#625=ORIENTED_EDGE('',*,*,#595,.F.);
#626=ORIENTED_EDGE('',*,*,#531,.T.);
#627=ORIENTED_EDGE('',*,*,#571,.F.);
#628=ORIENTED_EDGE('',*,*,#286,.T.);
#629=EDGE_LOOP('',(#625,#626,#627,#628));
#630=FACE_BOUND('',#629,.T.);
#631=ADVANCED_FACE('F876',(#630),#624,.T.);
#632=CARTESIAN_POINT('',(417.,22.7930444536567,117.5));
#633=DIRECTION('',(1.,0.,0.));
#634=DIRECTION('',(0.,0.,-1.));
#635=AXIS2_PLACEMENT_3D('',#632,#633,#634);
#636=PLANE('',#635);
#637=DIRECTION('',(0.,0.,1.));
#638=VECTOR('',#637,1.);
#639=CARTESIAN_POINT('',(417.,22.7930444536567,120.));
#640=LINE('',#639,#638);
#641=CARTESIAN_POINT('',(417.,22.7930444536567,118.5));
#642=VERTEX_POINT('',#641);
#643=CARTESIAN_POINT('',(417.,22.7930444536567,120.));
#644=VERTEX_POINT('',#643);
#645=EDGE_CURVE('E289',#642,#644,#640,.T.);
#646=ORIENTED_EDGE('',*,*,#645,.F.);
#647=CARTESIAN_POINT('',(417.,22.7930444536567,117.5));
#648=DIRECTION('',(1.,0.,0.));
#649=DIRECTION('',(0.,0.,-1.));
#650=AXIS2_PLACEMENT_3D('',#647,#648,#649);
#651=CIRCLE('',#650,1.);
#652=EDGE_CURVE('E291',#642,#177,#651,.F.);
#653=ORIENTED_EDGE('',*,*,#652,.T.);
#654=ORIENTED_EDGE('',*,*,#180,.T.);
#655=CARTESIAN_POINT('',(417.,22.7930444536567,117.5));
#656=DIRECTION('',(-1.,0.,0.));
#657=DIRECTION('',(0.,0.,1.));
#658=AXIS2_PLACEMENT_3D('',#655,#656,#657);
#659=CIRCLE('',#658,2.5);
#660=EDGE_CURVE('E315',#644,#179,#659,.T.);
#661=ORIENTED_EDGE('',*,*,#660,.F.);
#662=EDGE_LOOP('',(#646,#653,#654,#661));
#663=FACE_BOUND('',#662,.T.);
#664=ADVANCED_FACE('F872',(#663),#636,.T.);
#665=CARTESIAN_POINT('',(0.,22.7930444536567,117.5));
#666=DIRECTION('',(-1.,0.,0.));
#667=DIRECTION('',(0.,0.,1.));
#668=AXIS2_PLACEMENT_3D('',#665,#666,#667);
#669=PLANE('',#668);
#670=ORIENTED_EDGE('',*,*,#236,.F.);
#671=CARTESIAN_POINT('',(-1.11022302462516E-13,22.7930444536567,117.5));
#672=DIRECTION('',(1.,0.,0.));
#673=DIRECTION('',(0.,0.,-1.));
#674=AXIS2_PLACEMENT_3D('',#671,#672,#673);
#675=CIRCLE('',#674,1.);
#676=CARTESIAN_POINT('',(0.,22.7930444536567,118.5));
#677=VERTEX_POINT('',#676);
#678=EDGE_CURVE('E294',#227,#677,#675,.T.);
#679=ORIENTED_EDGE('',*,*,#678,.T.);
#680=DIRECTION('',(0.,0.,1.));
#681=VECTOR('',#680,1.);
#682=CARTESIAN_POINT('',(0.,22.7930444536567,120.));
#683=LINE('',#682,#681);
#684=CARTESIAN_POINT('',(0.,22.7930444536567,120.));
#685=VERTEX_POINT('',#684);
#686=EDGE_CURVE('E308',#677,#685,#683,.T.);
#687=ORIENTED_EDGE('',*,*,#686,.T.);
#688=CARTESIAN_POINT('',(0.,22.7930444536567,117.5));
#689=DIRECTION('',(1.,0.,0.));
#690=DIRECTION('',(0.,0.,-1.));
#691=AXIS2_PLACEMENT_3D('',#688,#689,#690);
#692=CIRCLE('',#691,2.50000000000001);
#693=EDGE_CURVE('E318',#235,#685,#692,.T.);
#694=ORIENTED_EDGE('',*,*,#693,.F.);
#695=EDGE_LOOP('',(#670,#679,#687,#694));
#696=FACE_BOUND('',#695,.T.);
#697=ADVANCED_FACE('F865',(#696),#669,.T.);
#698=CARTESIAN_POINT('',(-208.512621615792,22.7930444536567,117.5));
#699=DIRECTION('',(1.,0.,0.));
#700=DIRECTION('',(0.,0.,-1.));
#701=AXIS2_PLACEMENT_3D('',#698,#699,#700);
#702=CYLINDRICAL_SURFACE('',#701,2.5);
#703=ORIENTED_EDGE('',*,*,#693,.T.);
#704=DIRECTION('',(-1.,0.,0.));
#705=VECTOR('',#704,1.);
#706=CARTESIAN_POINT('',(-126.491106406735,22.7930444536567,120.));
#707=LINE('',#706,#705);
#708=EDGE_CURVE('E306',#644,#685,#707,.T.);
#709=ORIENTED_EDGE('',*,*,#708,.F.);
#710=ORIENTED_EDGE('',*,*,#660,.T.);
#711=ORIENTED_EDGE('',*,*,#264,.F.);
#712=EDGE_LOOP('',(#703,#709,#710,#711));
#713=FACE_BOUND('',#712,.T.);
#714=ADVANCED_FACE('F862',(#713),#702,.T.);
#715=CARTESIAN_POINT('',(-208.512621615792,22.7930444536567,117.5));
#716=DIRECTION('',(1.,0.,0.));
#717=DIRECTION('',(0.,0.,-1.));
#718=AXIS2_PLACEMENT_3D('',#715,#716,#717);
#719=CYLINDRICAL_SURFACE('',#718,1.);
#720=ORIENTED_EDGE('',*,*,#678,.F.);
#721=ORIENTED_EDGE('',*,*,#279,.T.);
#722=ORIENTED_EDGE('',*,*,#652,.F.);
#723=DIRECTION('',(-1.,0.,0.));
#724=VECTOR('',#723,1.);
#725=CARTESIAN_POINT('',(-126.491106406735,22.7930444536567,118.5));
#726=LINE('',#725,#724);
#727=EDGE_CURVE('E311',#642,#677,#726,.T.);
#728=ORIENTED_EDGE('',*,*,#727,.T.);
#729=EDGE_LOOP('',(#720,#721,#722,#728));
#730=FACE_BOUND('',#729,.T.);
#731=ADVANCED_FACE('F852',(#730),#719,.F.);
#732=CARTESIAN_POINT('',(-126.491106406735,0.,120.));
#733=DIRECTION('',(0.,0.,1.));
#734=DIRECTION('',(1.,0.,0.));
#735=AXIS2_PLACEMENT_3D('',#732,#733,#734);
#736=PLANE('',#735);
#737=DIRECTION('',(-1.,0.,0.));
#738=VECTOR('',#737,1.);
#739=CARTESIAN_POINT('',(0.,1.5,120.));
#740=LINE('',#739,#738);
#741=CARTESIAN_POINT('',(417.,1.5,120.));
#742=VERTEX_POINT('',#741);
#743=CARTESIAN_POINT('',(0.,1.5,120.));
#744=VERTEX_POINT('',#743);
#745=EDGE_CURVE('E272',#742,#744,#740,.T.);
#746=ORIENTED_EDGE('',*,*,#745,.F.);
#747=DIRECTION('',(0.,-1.,0.));
#748=VECTOR('',#747,1.);
#749=CARTESIAN_POINT('',(417.,0.,120.));
#750=LINE('',#749,#748);
#751=EDGE_CURVE('E283',#644,#742,#750,.T.);
#752=ORIENTED_EDGE('',*,*,#751,.F.);
#753=ORIENTED_EDGE('',*,*,#708,.T.);
#754=DIRECTION('',(0.,1.,0.));
#755=VECTOR('',#754,1.);
#756=CARTESIAN_POINT('',(0.,0.,120.));
#757=LINE('',#756,#755);
#758=EDGE_CURVE('E285',#744,#685,#757,.T.);
#759=ORIENTED_EDGE('',*,*,#758,.F.);
#760=EDGE_LOOP('',(#746,#752,#753,#759));
#761=FACE_BOUND('',#760,.T.);
#762=ADVANCED_FACE('F281',(#761),#736,.T.);
#763=CARTESIAN_POINT('',(0.,0.,120.));
#764=DIRECTION('',(1.,0.,0.));
#765=DIRECTION('',(0.,1.,0.));
#766=AXIS2_PLACEMENT_3D('',#763,#764,#765);
#767=PLANE('',#766);
#768=DIRECTION('',(0.,0.,1.));
#769=VECTOR('',#768,1.);
#770=CARTESIAN_POINT('',(0.,1.5,-127.501024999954));
#771=LINE('',#770,#769);
#772=CARTESIAN_POINT('',(0.,1.5,118.5));
#773=VERTEX_POINT('',#772);
#774=EDGE_CURVE('E277',#773,#744,#771,.T.);
#775=ORIENTED_EDGE('',*,*,#774,.T.);
#776=ORIENTED_EDGE('',*,*,#758,.T.);
#777=ORIENTED_EDGE('',*,*,#686,.F.);
#778=DIRECTION('',(0.,1.,0.));
#779=VECTOR('',#778,1.);
#780=CARTESIAN_POINT('',(0.,0.,118.5));
#781=LINE('',#780,#779);
#782=EDGE_CURVE('E296',#773,#677,#781,.T.);
#783=ORIENTED_EDGE('',*,*,#782,.F.);
#784=EDGE_LOOP('',(#775,#776,#777,#783));
#785=FACE_BOUND('',#784,.T.);
#786=ADVANCED_FACE('F851',(#785),#767,.F.);
#787=CARTESIAN_POINT('',(-126.491106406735,0.,118.5));
#788=DIRECTION('',(0.,0.,1.));
#789=DIRECTION('',(1.,0.,0.));
#790=AXIS2_PLACEMENT_3D('',#787,#788,#789);
#791=PLANE('',#790);
#792=DIRECTION('',(0.,1.,0.));
#793=VECTOR('',#792,1.);
#794=CARTESIAN_POINT('',(417.,0.,118.5));
#795=LINE('',#794,#793);
#796=CARTESIAN_POINT('',(417.,1.5,118.5));
#797=VERTEX_POINT('',#796);
#798=EDGE_CURVE('E303',#642,#797,#795,.F.);
#799=ORIENTED_EDGE('',*,*,#798,.T.);
#800=DIRECTION('',(1.,0.,0.));
#801=VECTOR('',#800,1.);
#802=CARTESIAN_POINT('',(2.25745980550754E-13,1.5,118.5));
#803=LINE('',#802,#801);
#804=EDGE_CURVE('E65',#773,#797,#803,.T.);
#805=ORIENTED_EDGE('',*,*,#804,.F.);
#806=ORIENTED_EDGE('',*,*,#782,.T.);
#807=ORIENTED_EDGE('',*,*,#727,.F.);
#808=EDGE_LOOP('',(#799,#805,#806,#807));
#809=FACE_BOUND('',#808,.T.);
#810=ADVANCED_FACE('F855',(#809),#791,.F.);
#811=CARTESIAN_POINT('',(417.,0.,120.));
#812=DIRECTION('',(-1.,0.,0.));
#813=DIRECTION('',(0.,-1.,0.));
#814=AXIS2_PLACEMENT_3D('',#811,#812,#813);
#815=PLANE('',#814);
#816=DIRECTION('',(0.,0.,1.));
#817=VECTOR('',#816,1.);
#818=CARTESIAN_POINT('',(417.,1.5,-127.501024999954));
#819=LINE('',#818,#817);
#820=EDGE_CURVE('E269',#797,#742,#819,.T.);
#821=ORIENTED_EDGE('',*,*,#820,.F.);
#822=ORIENTED_EDGE('',*,*,#798,.F.);
#823=ORIENTED_EDGE('',*,*,#645,.T.);
#824=ORIENTED_EDGE('',*,*,#751,.T.);
#825=EDGE_LOOP('',(#821,#822,#823,#824));
#826=FACE_BOUND('',#825,.T.);
#827=ADVANCED_FACE('F287',(#826),#815,.F.);
#828=CARTESIAN_POINT('',(1.07071068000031,337.5,-124.999999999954));
#829=DIRECTION('',(-1.,0.,0.));
#830=DIRECTION('',(0.,0.,1.));
#831=AXIS2_PLACEMENT_3D('',#828,#829,#830);
#832=PLANE('',#831);
#833=DIRECTION('',(0.,0.,-1.));
#834=VECTOR('',#833,1.);
#835=CARTESIAN_POINT('',(1.07071068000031,337.5,-126.000000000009));
#836=LINE('',#835,#834);
#837=CARTESIAN_POINT('',(1.07071068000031,337.5,-126.000000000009));
#838=VERTEX_POINT('',#837);
#839=CARTESIAN_POINT('',(1.07071068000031,337.5,-127.500000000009));
#840=VERTEX_POINT('',#839);
#841=EDGE_CURVE('E486',#838,#840,#836,.T.);
#842=ORIENTED_EDGE('',*,*,#841,.F.);
#843=CARTESIAN_POINT('',(1.07071068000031,337.5,-124.999999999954));
#844=DIRECTION('',(-1.,0.,0.));
#845=DIRECTION('',(0.,0.,1.));
#846=AXIS2_PLACEMENT_3D('',#843,#844,#845);
#847=CIRCLE('',#846,1.);
#848=EDGE_CURVE('E299',#838,#51,#847,.F.);
#849=ORIENTED_EDGE('',*,*,#848,.T.);
#850=ORIENTED_EDGE('',*,*,#300,.T.);
#851=CARTESIAN_POINT('',(1.07071068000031,337.5,-124.999999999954));
#852=DIRECTION('',(1.,0.,0.));
#853=DIRECTION('',(0.,0.,-1.));
#854=AXIS2_PLACEMENT_3D('',#851,#852,#853);
#855=CIRCLE('',#854,2.5);
#856=EDGE_CURVE('E471',#840,#125,#855,.T.);
#857=ORIENTED_EDGE('',*,*,#856,.F.);
#858=EDGE_LOOP('',(#842,#849,#850,#857));
#859=FACE_BOUND('',#858,.T.);
#860=ADVANCED_FACE('F664',(#859),#832,.T.);
#861=CARTESIAN_POINT('',(415.9292893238,337.5,-124.999999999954));
#862=DIRECTION('',(1.,0.,0.));
#863=DIRECTION('',(0.,0.,-1.));
#864=AXIS2_PLACEMENT_3D('',#861,#862,#863);
#865=PLANE('',#864);
#866=ORIENTED_EDGE('',*,*,#318,.F.);
#867=CARTESIAN_POINT('',(415.9292893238,337.5,-124.999999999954));
#868=DIRECTION('',(-1.,0.,0.));
#869=DIRECTION('',(0.,0.,1.));
#870=AXIS2_PLACEMENT_3D('',#867,#868,#869);
#871=CIRCLE('',#870,1.);
#872=CARTESIAN_POINT('',(415.9292893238,337.5,-126.000000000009));
#873=VERTEX_POINT('',#872);
#874=EDGE_CURVE('E473',#61,#873,#871,.T.);
#875=ORIENTED_EDGE('',*,*,#874,.T.);
#876=DIRECTION('',(0.,0.,-1.));
#877=VECTOR('',#876,1.);
#878=CARTESIAN_POINT('',(415.9292893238,337.5,-126.000000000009));
#879=LINE('',#878,#877);
#880=CARTESIAN_POINT('',(415.9292893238,337.499999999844,-127.499999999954));
#881=VERTEX_POINT('',#880);
#882=EDGE_CURVE('E490',#873,#881,#879,.T.);
#883=ORIENTED_EDGE('',*,*,#882,.T.);
#884=CARTESIAN_POINT('',(415.9292893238,337.5,-124.999999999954));
#885=DIRECTION('',(-1.,0.,0.));
#886=DIRECTION('',(0.,0.,1.));
#887=AXIS2_PLACEMENT_3D('',#884,#885,#886);
#888=CIRCLE('',#887,2.5);
#889=EDGE_CURVE('E314',#127,#881,#888,.T.);
#890=ORIENTED_EDGE('',*,*,#889,.F.);
#891=EDGE_LOOP('',(#866,#875,#883,#890));
#892=FACE_BOUND('',#891,.T.);
#893=ADVANCED_FACE('F673',(#892),#865,.T.);
#894=CARTESIAN_POINT('',(623.370397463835,337.5,-124.999999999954));
#895=DIRECTION('',(-1.,0.,0.));
#896=DIRECTION('',(0.,0.,1.));
#897=AXIS2_PLACEMENT_3D('',#894,#895,#896);
#898=CYLINDRICAL_SURFACE('',#897,2.5);
#899=ORIENTED_EDGE('',*,*,#889,.T.);
#900=DIRECTION('',(1.,0.,0.));
#901=VECTOR('',#900,1.);
#902=CARTESIAN_POINT('',(0.,337.500000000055,-127.500000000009));
#903=LINE('',#902,#901);
#904=EDGE_CURVE('E612',#840,#881,#903,.T.);
#905=ORIENTED_EDGE('',*,*,#904,.F.);
#906=ORIENTED_EDGE('',*,*,#856,.T.);
#907=ORIENTED_EDGE('',*,*,#128,.T.);
#908=EDGE_LOOP('',(#899,#905,#906,#907));
#909=FACE_BOUND('',#908,.T.);
#910=ADVANCED_FACE('F840',(#909),#898,.T.);
#911=CARTESIAN_POINT('',(623.370397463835,337.5,-124.999999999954));
#912=DIRECTION('',(-1.,0.,0.));
#913=DIRECTION('',(0.,0.,1.));
#914=AXIS2_PLACEMENT_3D('',#911,#912,#913);
#915=CYLINDRICAL_SURFACE('',#914,1.);
#916=ORIENTED_EDGE('',*,*,#874,.F.);
#917=ORIENTED_EDGE('',*,*,#62,.F.);
#918=ORIENTED_EDGE('',*,*,#848,.F.);
#919=DIRECTION('',(1.,0.,0.));
#920=VECTOR('',#919,1.);
#921=CARTESIAN_POINT('',(0.,337.500000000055,-126.000000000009));
#922=LINE('',#921,#920);
#923=EDGE_CURVE('E488',#838,#873,#922,.T.);
#924=ORIENTED_EDGE('',*,*,#923,.T.);
#925=EDGE_LOOP('',(#916,#917,#918,#924));
#926=FACE_BOUND('',#925,.T.);
#927=ADVANCED_FACE('F671',(#926),#915,.F.);
#928=CARTESIAN_POINT('',(32.0707106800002,306.500000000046,-114.500000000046));
#929=DIRECTION('',(0.,-1.,0.));
#930=DIRECTION('',(0.,0.,-1.));
#931=AXIS2_PLACEMENT_3D('',#928,#929,#930);
#932=PLANE('',#931);
#933=DIRECTION('',(-1.,0.,0.));
#934=VECTOR('',#933,1.);
#935=CARTESIAN_POINT('',(32.0707106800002,306.500000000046,-116.000000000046));
#936=LINE('',#935,#934);
#937=CARTESIAN_POINT('',(384.9292893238,306.500000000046,-116.000000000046));
#938=VERTEX_POINT('',#937);
#939=CARTESIAN_POINT('',(32.0707106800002,306.500000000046,-116.000000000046));
#940=VERTEX_POINT('',#939);
#941=EDGE_CURVE('E512',#938,#940,#936,.T.);
#942=ORIENTED_EDGE('',*,*,#941,.F.);
#943=DIRECTION('',(0.,0.,-1.));
#944=VECTOR('',#943,1.);
#945=CARTESIAN_POINT('',(384.9292893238,306.500000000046,-114.500000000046));
#946=LINE('',#945,#944);
#947=CARTESIAN_POINT('',(384.9292893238,306.500000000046,-114.500000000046));
#948=VERTEX_POINT('',#947);
#949=EDGE_CURVE('E504',#948,#938,#946,.T.);
#950=ORIENTED_EDGE('',*,*,#949,.F.);
#951=DIRECTION('',(-1.,0.,0.));
#952=VECTOR('',#951,1.);
#953=CARTESIAN_POINT('',(32.0707106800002,306.500000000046,-114.500000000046));
#954=LINE('',#953,#952);
#955=CARTESIAN_POINT('',(32.0707106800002,306.500000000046,-114.500000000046));
#956=VERTEX_POINT('',#955);
#957=EDGE_CURVE('E492',#948,#956,#954,.T.);
#958=ORIENTED_EDGE('',*,*,#957,.T.);
#959=DIRECTION('',(0.,0.,-1.));
#960=VECTOR('',#959,1.);
#961=CARTESIAN_POINT('',(32.0707106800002,306.500000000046,-114.500000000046));
#962=LINE('',#961,#960);
#963=EDGE_CURVE('E495',#956,#940,#962,.T.);
#964=ORIENTED_EDGE('',*,*,#963,.T.);
#965=EDGE_LOOP('',(#942,#950,#958,#964));
#966=FACE_BOUND('',#965,.T.);
#967=ADVANCED_FACE('F741',(#966),#932,.T.);
#968=CARTESIAN_POINT('',(32.0707106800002,306.500000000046,-114.500000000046));
#969=DIRECTION('',(-0.707106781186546,-0.707106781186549,0.));
#970=DIRECTION('',(-0.707106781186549,0.707106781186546,0.));
#971=AXIS2_PLACEMENT_3D('',#968,#969,#970);
#972=PLANE('',#971);
#973=DIRECTION('',(-0.707106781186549,0.707106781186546,0.));
#974=VECTOR('',#973,1.);
#975=CARTESIAN_POINT('',(32.0707106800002,306.500000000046,-116.000000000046));
#976=LINE('',#975,#974);
#977=CARTESIAN_POINT('',(14.5707106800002,323.999999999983,-116.0000000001));
#978=VERTEX_POINT('',#977);
#979=EDGE_CURVE('E515',#940,#978,#976,.T.);
#980=ORIENTED_EDGE('',*,*,#979,.F.);
#981=ORIENTED_EDGE('',*,*,#963,.F.);
#982=DIRECTION('',(-0.707106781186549,0.707106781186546,0.));
#983=VECTOR('',#982,1.);
#984=CARTESIAN_POINT('',(32.0707106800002,306.500000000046,-114.500000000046));
#985=LINE('',#984,#983);
#986=CARTESIAN_POINT('',(14.5707106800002,324.000000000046,-114.500000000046));
#987=VERTEX_POINT('',#986);
#988=EDGE_CURVE('E497',#956,#987,#985,.T.);
#989=ORIENTED_EDGE('',*,*,#988,.T.);
#990=DIRECTION('',(0.,0.,-1.));
#991=VECTOR('',#990,1.);
#992=CARTESIAN_POINT('',(14.5707106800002,324.000000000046,-114.500000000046));
#993=LINE('',#992,#991);
#994=EDGE_CURVE('E499',#987,#978,#993,.T.);
#995=ORIENTED_EDGE('',*,*,#994,.T.);
#996=EDGE_LOOP('',(#980,#981,#989,#995));
#997=FACE_BOUND('',#996,.T.);
#998=ADVANCED_FACE('F744',(#997),#972,.T.);
#999=CARTESIAN_POINT('',(384.9292893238,306.500000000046,-114.500000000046));
#1000=DIRECTION('',(0.707106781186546,-0.707106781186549,0.));
#1001=DIRECTION('',(-0.707106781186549,-0.707106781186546,0.));
#1002=AXIS2_PLACEMENT_3D('',#999,#1000,#1001);
#1003=PLANE('',#1002);
#1004=DIRECTION('',(-0.707106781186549,-0.707106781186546,0.));
#1005=VECTOR('',#1004,1.);
#1006=CARTESIAN_POINT('',(384.9292893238,306.500000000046,-116.000000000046));
#1007=LINE('',#1006,#1005);
#1008=CARTESIAN_POINT('',(402.4292893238,324.000000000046,-116.000000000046));
#1009=VERTEX_POINT('',#1008);
#1010=EDGE_CURVE('E509',#1009,#938,#1007,.T.);
#1011=ORIENTED_EDGE('',*,*,#1010,.F.);
#1012=DIRECTION('',(0.,0.,-1.));
#1013=VECTOR('',#1012,1.);
#1014=CARTESIAN_POINT('',(402.4292893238,324.000000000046,-114.500000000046));
#1015=LINE('',#1014,#1013);
#1016=CARTESIAN_POINT('',(402.4292893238,324.000000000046,-114.500000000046));
#1017=VERTEX_POINT('',#1016);
#1018=EDGE_CURVE('E527',#1017,#1009,#1015,.T.);
#1019=ORIENTED_EDGE('',*,*,#1018,.F.);
#1020=DIRECTION('',(-0.707106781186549,-0.707106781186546,0.));
#1021=VECTOR('',#1020,1.);
#1022=CARTESIAN_POINT('',(384.9292893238,306.500000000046,-114.500000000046));
#1023=LINE('',#1022,#1021);
#1024=EDGE_CURVE('E501',#1017,#948,#1023,.T.);
#1025=ORIENTED_EDGE('',*,*,#1024,.T.);
#1026=ORIENTED_EDGE('',*,*,#949,.T.);
#1027=EDGE_LOOP('',(#1011,#1019,#1025,#1026));
#1028=FACE_BOUND('',#1027,.T.);
#1029=ADVANCED_FACE('F748',(#1028),#1003,.T.);
#1030=CARTESIAN_POINT('',(0.,350.246680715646,-114.500000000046));
#1031=DIRECTION('',(0.,0.,1.));
#1032=DIRECTION('',(0.,-1.,0.));
#1033=AXIS2_PLACEMENT_3D('',#1030,#1031,#1032);
#1034=PLANE('',#1033);
#1035=ORIENTED_EDGE('',*,*,#1024,.F.);
#1036=DIRECTION('',(-1.,0.,0.));
#1037=VECTOR('',#1036,1.);
#1038=CARTESIAN_POINT('',(0.,324.0000000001,-114.500000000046));
#1039=LINE('',#1038,#1037);
#1040=EDGE_CURVE('E506',#1017,#987,#1039,.T.);
#1041=ORIENTED_EDGE('',*,*,#1040,.T.);
#1042=ORIENTED_EDGE('',*,*,#988,.F.);
#1043=ORIENTED_EDGE('',*,*,#957,.F.);
#1044=EDGE_LOOP('',(#1035,#1041,#1042,#1043));
#1045=FACE_BOUND('',#1044,.T.);
#1046=ADVANCED_FACE('F752',(#1045),#1034,.T.);
#1047=CARTESIAN_POINT('',(0.,350.246680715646,-116.000000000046));
#1048=DIRECTION('',(0.,0.,1.));
#1049=DIRECTION('',(0.,-1.,0.));
#1050=AXIS2_PLACEMENT_3D('',#1047,#1048,#1049);
#1051=PLANE('',#1050);
#1052=DIRECTION('',(-1.,0.,0.));
#1053=VECTOR('',#1052,1.);
#1054=CARTESIAN_POINT('',(0.,324.0000000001,-116.000000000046));
#1055=LINE('',#1054,#1053);
#1056=EDGE_CURVE('E544',#1009,#978,#1055,.T.);
#1057=ORIENTED_EDGE('',*,*,#1056,.F.);
#1058=ORIENTED_EDGE('',*,*,#1010,.T.);
#1059=ORIENTED_EDGE('',*,*,#941,.T.);
#1060=ORIENTED_EDGE('',*,*,#979,.T.);
#1061=EDGE_LOOP('',(#1057,#1058,#1059,#1060));
#1062=FACE_BOUND('',#1061,.T.);
#1063=ADVANCED_FACE('F756',(#1062),#1051,.F.);
#1064=CARTESIAN_POINT('',(14.5707106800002,324.000000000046,-117.0000000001));
#1065=DIRECTION('',(1.,0.,0.));
#1066=DIRECTION('',(0.,0.,1.));
#1067=AXIS2_PLACEMENT_3D('',#1064,#1065,#1066);
#1068=PLANE('',#1067);
#1069=ORIENTED_EDGE('',*,*,#994,.F.);
#1070=CARTESIAN_POINT('',(14.5707106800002,324.000000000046,-117.0000000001));
#1071=DIRECTION('',(-1.,0.,0.));
#1072=DIRECTION('',(0.,0.,-1.));
#1073=AXIS2_PLACEMENT_3D('',#1070,#1071,#1072);
#1074=CIRCLE('',#1073,2.5);
#1075=CARTESIAN_POINT('',(14.5707106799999,326.500000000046,-117.000000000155));
#1076=VERTEX_POINT('',#1075);
#1077=EDGE_CURVE('E518',#987,#1076,#1074,.T.);
#1078=ORIENTED_EDGE('',*,*,#1077,.T.);
#1079=DIRECTION('',(0.,-1.,0.));
#1080=VECTOR('',#1079,1.);
#1081=CARTESIAN_POINT('',(14.5707106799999,326.500000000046,-117.000000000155));
#1082=LINE('',#1081,#1080);
#1083=CARTESIAN_POINT('',(14.5707106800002,325.000000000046,-117.000000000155));
#1084=VERTEX_POINT('',#1083);
#1085=EDGE_CURVE('E521',#1076,#1084,#1082,.T.);
#1086=ORIENTED_EDGE('',*,*,#1085,.T.);
#1087=CARTESIAN_POINT('',(14.5707106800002,324.000000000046,-117.0000000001));
#1088=DIRECTION('',(-1.,0.,0.));
#1089=DIRECTION('',(0.,0.,-1.));
#1090=AXIS2_PLACEMENT_3D('',#1087,#1088,#1089);
#1091=CIRCLE('',#1090,0.999999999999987);
#1092=EDGE_CURVE('E538',#978,#1084,#1091,.T.);
#1093=ORIENTED_EDGE('',*,*,#1092,.F.);
#1094=EDGE_LOOP('',(#1069,#1078,#1086,#1093));
#1095=FACE_BOUND('',#1094,.T.);
#1096=ADVANCED_FACE('F760',(#1095),#1068,.F.);
#1097=CARTESIAN_POINT('',(402.4292893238,324.000000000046,-117.0000000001));
#1098=DIRECTION('',(-1.,0.,0.));
#1099=DIRECTION('',(0.,0.,-1.));
#1100=AXIS2_PLACEMENT_3D('',#1097,#1098,#1099);
#1101=PLANE('',#1100);
#1102=DIRECTION('',(0.,-1.,0.));
#1103=VECTOR('',#1102,1.);
#1104=CARTESIAN_POINT('',(402.4292893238,326.500000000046,-117.000000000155));
#1105=LINE('',#1104,#1103);
#1106=CARTESIAN_POINT('',(402.4292893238,326.500000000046,-117.000000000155));
#1107=VERTEX_POINT('',#1106);
#1108=CARTESIAN_POINT('',(402.4292893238,325.000000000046,-117.000000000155));
#1109=VERTEX_POINT('',#1108);
#1110=EDGE_CURVE('E549',#1107,#1109,#1105,.T.);
#1111=ORIENTED_EDGE('',*,*,#1110,.F.);
#1112=CARTESIAN_POINT('',(402.4292893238,324.000000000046,-117.0000000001));
#1113=DIRECTION('',(-1.,0.,0.));
#1114=DIRECTION('',(0.,0.,-1.));
#1115=AXIS2_PLACEMENT_3D('',#1112,#1113,#1114);
#1116=CIRCLE('',#1115,2.5);
#1117=EDGE_CURVE('E524',#1107,#1017,#1116,.F.);
#1118=ORIENTED_EDGE('',*,*,#1117,.T.);
#1119=ORIENTED_EDGE('',*,*,#1018,.T.);
#1120=CARTESIAN_POINT('',(402.4292893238,324.000000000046,-117.0000000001));
#1121=DIRECTION('',(1.,0.,0.));
#1122=DIRECTION('',(0.,0.,1.));
#1123=AXIS2_PLACEMENT_3D('',#1120,#1121,#1122);
#1124=CIRCLE('',#1123,0.999999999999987);
#1125=EDGE_CURVE('E541',#1109,#1009,#1124,.T.);
#1126=ORIENTED_EDGE('',*,*,#1125,.F.);
#1127=EDGE_LOOP('',(#1111,#1118,#1119,#1126));
#1128=FACE_BOUND('',#1127,.T.);
#1129=ADVANCED_FACE('F764',(#1128),#1101,.F.);
#1130=CARTESIAN_POINT('',(596.371220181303,324.000000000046,-117.0000000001));
#1131=DIRECTION('',(-1.,0.,0.));
#1132=DIRECTION('',(0.,0.,-1.));
#1133=AXIS2_PLACEMENT_3D('',#1130,#1131,#1132);
#1134=CYLINDRICAL_SURFACE('',#1133,2.5);
#1135=ORIENTED_EDGE('',*,*,#1077,.F.);
#1136=ORIENTED_EDGE('',*,*,#1040,.F.);
#1137=ORIENTED_EDGE('',*,*,#1117,.F.);
#1138=DIRECTION('',(-1.,0.,0.));
#1139=VECTOR('',#1138,1.);
#1140=CARTESIAN_POINT('',(0.,326.500000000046,-117.0000000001));
#1141=LINE('',#1140,#1139);
#1142=EDGE_CURVE('E530',#1107,#1076,#1141,.T.);
#1143=ORIENTED_EDGE('',*,*,#1142,.T.);
#1144=EDGE_LOOP('',(#1135,#1136,#1137,#1143));
#1145=FACE_BOUND('',#1144,.T.);
#1146=ADVANCED_FACE('F768',(#1145),#1134,.T.);
#1147=CARTESIAN_POINT('',(13.5000000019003,326.500000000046,-117.000000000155));
#1148=DIRECTION('',(0.,0.,1.));
#1149=DIRECTION('',(0.,-1.,0.));
#1150=AXIS2_PLACEMENT_3D('',#1147,#1148,#1149);
#1151=PLANE('',#1150);
#1152=DIRECTION('',(-1.,0.,0.));
#1153=VECTOR('',#1152,1.);
#1154=CARTESIAN_POINT('',(13.5000000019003,325.000000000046,-117.000000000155));
#1155=LINE('',#1154,#1153);
#1156=CARTESIAN_POINT('',(13.5000000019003,325.000000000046,-117.000000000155));
#1157=VERTEX_POINT('',#1156);
#1158=EDGE_CURVE('E576',#1084,#1157,#1155,.T.);
#1159=ORIENTED_EDGE('',*,*,#1158,.F.);
#1160=ORIENTED_EDGE('',*,*,#1085,.F.);
#1161=DIRECTION('',(-1.,0.,0.));
#1162=VECTOR('',#1161,1.);
#1163=CARTESIAN_POINT('',(13.5000000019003,326.500000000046,-117.000000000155));
#1164=LINE('',#1163,#1162);
#1165=CARTESIAN_POINT('',(13.5000000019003,326.500000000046,-117.000000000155));
#1166=VERTEX_POINT('',#1165);
#1167=EDGE_CURVE('E533',#1076,#1166,#1164,.T.);
#1168=ORIENTED_EDGE('',*,*,#1167,.T.);
#1169=DIRECTION('',(0.,-1.,0.));
#1170=VECTOR('',#1169,1.);
#1171=CARTESIAN_POINT('',(13.5000000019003,326.500000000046,-117.000000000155));
#1172=LINE('',#1171,#1170);
#1173=EDGE_CURVE('E536',#1166,#1157,#1172,.T.);
#1174=ORIENTED_EDGE('',*,*,#1173,.T.);
#1175=EDGE_LOOP('',(#1159,#1160,#1168,#1174));
#1176=FACE_BOUND('',#1175,.T.);
#1177=ADVANCED_FACE('F772',(#1176),#1151,.T.);
#1178=CARTESIAN_POINT('',(596.371220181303,324.000000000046,-117.0000000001));
#1179=DIRECTION('',(-1.,0.,0.));
#1180=DIRECTION('',(0.,0.,-1.));
#1181=AXIS2_PLACEMENT_3D('',#1178,#1179,#1180);
#1182=CYLINDRICAL_SURFACE('',#1181,1.);
#1183=ORIENTED_EDGE('',*,*,#1092,.T.);
#1184=DIRECTION('',(-1.,0.,0.));
#1185=VECTOR('',#1184,1.);
#1186=CARTESIAN_POINT('',(0.,325.000000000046,-117.0000000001));
#1187=LINE('',#1186,#1185);
#1188=EDGE_CURVE('E573',#1109,#1084,#1187,.T.);
#1189=ORIENTED_EDGE('',*,*,#1188,.F.);
#1190=ORIENTED_EDGE('',*,*,#1125,.T.);
#1191=ORIENTED_EDGE('',*,*,#1056,.T.);
#1192=EDGE_LOOP('',(#1183,#1189,#1190,#1191));
#1193=FACE_BOUND('',#1192,.T.);
#1194=ADVANCED_FACE('F776',(#1193),#1182,.F.);
#1195=CARTESIAN_POINT('',(403.5000000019,326.500000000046,-117.000000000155));
#1196=DIRECTION('',(0.,0.,1.));
#1197=DIRECTION('',(0.,-1.,0.));
#1198=AXIS2_PLACEMENT_3D('',#1195,#1196,#1197);
#1199=PLANE('',#1198);
#1200=DIRECTION('',(-1.,0.,0.));
#1201=VECTOR('',#1200,1.);
#1202=CARTESIAN_POINT('',(403.5000000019,325.000000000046,-117.000000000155));
#1203=LINE('',#1202,#1201);
#1204=CARTESIAN_POINT('',(403.5000000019,325.000000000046,-117.000000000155));
#1205=VERTEX_POINT('',#1204);
#1206=EDGE_CURVE('E571',#1205,#1109,#1203,.T.);
#1207=ORIENTED_EDGE('',*,*,#1206,.F.);
#1208=DIRECTION('',(0.,-1.,0.));
#1209=VECTOR('',#1208,1.);
#1210=CARTESIAN_POINT('',(403.5000000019,326.500000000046,-117.000000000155));
#1211=LINE('',#1210,#1209);
#1212=CARTESIAN_POINT('',(403.5000000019,326.500000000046,-117.000000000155));
#1213=VERTEX_POINT('',#1212);
#1214=EDGE_CURVE('E556',#1213,#1205,#1211,.T.);
#1215=ORIENTED_EDGE('',*,*,#1214,.F.);
#1216=DIRECTION('',(-1.,0.,0.));
#1217=VECTOR('',#1216,1.);
#1218=CARTESIAN_POINT('',(403.5000000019,326.500000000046,-117.000000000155));
#1219=LINE('',#1218,#1217);
#1220=EDGE_CURVE('E547',#1213,#1107,#1219,.T.);
#1221=ORIENTED_EDGE('',*,*,#1220,.T.);
#1222=ORIENTED_EDGE('',*,*,#1110,.T.);
#1223=EDGE_LOOP('',(#1207,#1215,#1221,#1222));
#1224=FACE_BOUND('',#1223,.T.);
#1225=ADVANCED_FACE('F780',(#1224),#1199,.T.);
#1226=CARTESIAN_POINT('',(13.5000000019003,326.500000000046,-128.173518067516));
#1227=DIRECTION('',(-1.,0.,0.));
#1228=DIRECTION('',(0.,-1.,0.));
#1229=AXIS2_PLACEMENT_3D('',#1226,#1227,#1228);
#1230=PLANE('',#1229);
#1231=DIRECTION('',(0.,1.,0.));
#1232=VECTOR('',#1231,1.);
#1233=CARTESIAN_POINT('',(13.5000000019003,326.500000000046,-125.000000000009));
#1234=LINE('',#1233,#1232);
#1235=CARTESIAN_POINT('',(13.5000000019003,325.000000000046,-125.000000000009));
#1236=VERTEX_POINT('',#1235);
#1237=CARTESIAN_POINT('',(13.5000000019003,326.500000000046,-125.000000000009));
#1238=VERTEX_POINT('',#1237);
#1239=EDGE_CURVE('E559',#1236,#1238,#1234,.T.);
#1240=ORIENTED_EDGE('',*,*,#1239,.F.);
#1241=DIRECTION('',(0.,0.,-1.));
#1242=VECTOR('',#1241,1.);
#1243=CARTESIAN_POINT('',(13.5000000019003,325.000000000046,-128.173518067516));
#1244=LINE('',#1243,#1242);
#1245=EDGE_CURVE('E564',#1157,#1236,#1244,.T.);
#1246=ORIENTED_EDGE('',*,*,#1245,.F.);
#1247=ORIENTED_EDGE('',*,*,#1173,.F.);
#1248=DIRECTION('',(0.,0.,-1.));
#1249=VECTOR('',#1248,1.);
#1250=CARTESIAN_POINT('',(13.5000000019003,326.500000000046,-128.173518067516));
#1251=LINE('',#1250,#1249);
#1252=EDGE_CURVE('E552',#1166,#1238,#1251,.T.);
#1253=ORIENTED_EDGE('',*,*,#1252,.T.);
#1254=EDGE_LOOP('',(#1240,#1246,#1247,#1253));
#1255=FACE_BOUND('',#1254,.T.);
#1256=ADVANCED_FACE('F784',(#1255),#1230,.T.);
#1257=CARTESIAN_POINT('',(403.5000000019,326.500000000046,-128.173518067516));
#1258=DIRECTION('',(1.,0.,0.));
#1259=DIRECTION('',(0.,1.,0.));
#1260=AXIS2_PLACEMENT_3D('',#1257,#1258,#1259);
#1261=PLANE('',#1260);
#1262=DIRECTION('',(0.,-1.,0.));
#1263=VECTOR('',#1262,1.);
#1264=CARTESIAN_POINT('',(403.5000000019,326.500000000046,-125.000000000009));
#1265=LINE('',#1264,#1263);
#1266=CARTESIAN_POINT('',(403.5000000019,326.500000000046,-125.000000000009));
#1267=VERTEX_POINT('',#1266);
#1268=CARTESIAN_POINT('',(403.5000000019,325.000000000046,-125.000000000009));
#1269=VERTEX_POINT('',#1268);
#1270=EDGE_CURVE('E582',#1267,#1269,#1265,.T.);
#1271=ORIENTED_EDGE('',*,*,#1270,.F.);
#1272=DIRECTION('',(0.,0.,1.));
#1273=VECTOR('',#1272,1.);
#1274=CARTESIAN_POINT('',(403.5000000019,326.500000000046,-128.173518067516));
#1275=LINE('',#1274,#1273);
#1276=EDGE_CURVE('E554',#1267,#1213,#1275,.T.);
#1277=ORIENTED_EDGE('',*,*,#1276,.T.);
#1278=ORIENTED_EDGE('',*,*,#1214,.T.);
#1279=DIRECTION('',(0.,0.,1.));
#1280=VECTOR('',#1279,1.);
#1281=CARTESIAN_POINT('',(403.5000000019,325.000000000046,-128.173518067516));
#1282=LINE('',#1281,#1280);
#1283=EDGE_CURVE('E569',#1269,#1205,#1282,.T.);
#1284=ORIENTED_EDGE('',*,*,#1283,.F.);
#1285=EDGE_LOOP('',(#1271,#1277,#1278,#1284));
#1286=FACE_BOUND('',#1285,.T.);
#1287=ADVANCED_FACE('F788',(#1286),#1261,.T.);
#1288=CARTESIAN_POINT('',(0.,326.500000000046,-140.497787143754));
#1289=DIRECTION('',(0.,1.,0.));
#1290=DIRECTION('',(0.,0.,1.));
#1291=AXIS2_PLACEMENT_3D('',#1288,#1289,#1290);
#1292=PLANE('',#1291);
#1293=DIRECTION('',(1.,0.,0.));
#1294=VECTOR('',#1293,1.);
#1295=CARTESIAN_POINT('',(0.,326.500000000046,-125.000000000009));
#1296=LINE('',#1295,#1294);
#1297=EDGE_CURVE('E585',#1238,#1267,#1296,.T.);
#1298=ORIENTED_EDGE('',*,*,#1297,.F.);
#1299=ORIENTED_EDGE('',*,*,#1252,.F.);
#1300=ORIENTED_EDGE('',*,*,#1167,.F.);
#1301=ORIENTED_EDGE('',*,*,#1142,.F.);
#1302=ORIENTED_EDGE('',*,*,#1220,.F.);
#1303=ORIENTED_EDGE('',*,*,#1276,.F.);
#1304=EDGE_LOOP('',(#1298,#1299,#1300,#1301,#1302,#1303));
#1305=FACE_BOUND('',#1304,.T.);
#1306=ADVANCED_FACE('F792',(#1305),#1292,.T.);
#1307=CARTESIAN_POINT('',(13.5000000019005,327.500000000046,-125.000000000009));
#1308=DIRECTION('',(-1.,0.,0.));
#1309=DIRECTION('',(0.,1.,0.));
#1310=AXIS2_PLACEMENT_3D('',#1307,#1308,#1309);
#1311=PLANE('',#1310);
#1312=ORIENTED_EDGE('',*,*,#1239,.T.);
#1313=CARTESIAN_POINT('',(13.5000000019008,327.500000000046,-125.000000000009));
#1314=DIRECTION('',(-1.,0.,0.));
#1315=DIRECTION('',(0.,1.,0.));
#1316=AXIS2_PLACEMENT_3D('',#1313,#1314,#1315);
#1317=CIRCLE('',#1316,1.);
#1318=CARTESIAN_POINT('',(13.5000000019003,327.500000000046,-126.000000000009));
#1319=VERTEX_POINT('',#1318);
#1320=EDGE_CURVE('E562',#1238,#1319,#1317,.F.);
#1321=ORIENTED_EDGE('',*,*,#1320,.T.);
#1322=DIRECTION('',(0.,0.,1.));
#1323=VECTOR('',#1322,1.);
#1324=CARTESIAN_POINT('',(13.5000000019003,327.500000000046,-126.000000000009));
#1325=LINE('',#1324,#1323);
#1326=CARTESIAN_POINT('',(13.5000000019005,327.500000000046,-127.500000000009));
#1327=VERTEX_POINT('',#1326);
#1328=EDGE_CURVE('E588',#1327,#1319,#1325,.T.);
#1329=ORIENTED_EDGE('',*,*,#1328,.F.);
#1330=CARTESIAN_POINT('',(13.5000000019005,327.500000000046,-125.000000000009));
#1331=DIRECTION('',(1.,0.,0.));
#1332=DIRECTION('',(0.,-1.,0.));
#1333=AXIS2_PLACEMENT_3D('',#1330,#1331,#1332);
#1334=CIRCLE('',#1333,2.5);
#1335=EDGE_CURVE('E599',#1236,#1327,#1334,.T.);
#1336=ORIENTED_EDGE('',*,*,#1335,.F.);
#1337=EDGE_LOOP('',(#1312,#1321,#1329,#1336));
#1338=FACE_BOUND('',#1337,.T.);
#1339=ADVANCED_FACE('F796',(#1338),#1311,.T.);
#1340=CARTESIAN_POINT('',(0.,325.000000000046,-140.497787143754));
#1341=DIRECTION('',(0.,1.,0.));
#1342=DIRECTION('',(0.,0.,1.));
#1343=AXIS2_PLACEMENT_3D('',#1340,#1341,#1342);
#1344=PLANE('',#1343);
#1345=ORIENTED_EDGE('',*,*,#1245,.T.);
#1346=DIRECTION('',(1.,0.,0.));
#1347=VECTOR('',#1346,1.);
#1348=CARTESIAN_POINT('',(0.,325.000000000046,-125.000000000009));
#1349=LINE('',#1348,#1347);
#1350=EDGE_CURVE('E566',#1236,#1269,#1349,.T.);
#1351=ORIENTED_EDGE('',*,*,#1350,.T.);
#1352=ORIENTED_EDGE('',*,*,#1283,.T.);
#1353=ORIENTED_EDGE('',*,*,#1206,.T.);
#1354=ORIENTED_EDGE('',*,*,#1188,.T.);
#1355=ORIENTED_EDGE('',*,*,#1158,.T.);
#1356=EDGE_LOOP('',(#1345,#1351,#1352,#1353,#1354,#1355));
#1357=FACE_BOUND('',#1356,.T.);
#1358=ADVANCED_FACE('F800',(#1357),#1344,.F.);
#1359=CARTESIAN_POINT('',(403.5000000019,327.500000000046,-125.000000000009));
#1360=DIRECTION('',(1.,0.,0.));
#1361=DIRECTION('',(0.,-1.,0.));
#1362=AXIS2_PLACEMENT_3D('',#1359,#1360,#1361);
#1363=PLANE('',#1362);
#1364=DIRECTION('',(0.,0.,-1.));
#1365=VECTOR('',#1364,1.);
#1366=CARTESIAN_POINT('',(403.5000000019,327.500000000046,-126.000000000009));
#1367=LINE('',#1366,#1365);
#1368=CARTESIAN_POINT('',(403.5000000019,327.500000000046,-126.000000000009));
#1369=VERTEX_POINT('',#1368);
#1370=CARTESIAN_POINT('',(403.5000000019,327.500000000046,-127.500000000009));
#1371=VERTEX_POINT('',#1370);
#1372=EDGE_CURVE('E607',#1369,#1371,#1367,.T.);
#1373=ORIENTED_EDGE('',*,*,#1372,.F.);
#1374=CARTESIAN_POINT('',(403.5000000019,327.500000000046,-125.000000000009));
#1375=DIRECTION('',(-1.,0.,0.));
#1376=DIRECTION('',(0.,1.,0.));
#1377=AXIS2_PLACEMENT_3D('',#1374,#1375,#1376);
#1378=CIRCLE('',#1377,1.);
#1379=EDGE_CURVE('E579',#1369,#1267,#1378,.T.);
#1380=ORIENTED_EDGE('',*,*,#1379,.T.);
#1381=ORIENTED_EDGE('',*,*,#1270,.T.);
#1382=CARTESIAN_POINT('',(403.5000000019,327.500000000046,-125.000000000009));
#1383=DIRECTION('',(-1.,0.,0.));
#1384=DIRECTION('',(0.,1.,0.));
#1385=AXIS2_PLACEMENT_3D('',#1382,#1383,#1384);
#1386=CIRCLE('',#1385,2.5);
#1387=EDGE_CURVE('E596',#1371,#1269,#1386,.T.);
#1388=ORIENTED_EDGE('',*,*,#1387,.F.);
#1389=EDGE_LOOP('',(#1373,#1380,#1381,#1388));
#1390=FACE_BOUND('',#1389,.T.);
#1391=ADVANCED_FACE('F804',(#1390),#1363,.T.);
#1392=CARTESIAN_POINT('',(598.512572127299,327.500000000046,-125.000000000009));
#1393=DIRECTION('',(-1.,0.,0.));
#1394=DIRECTION('',(0.,1.,0.));
#1395=AXIS2_PLACEMENT_3D('',#1392,#1393,#1394);
#1396=CYLINDRICAL_SURFACE('',#1395,1.);
#1397=ORIENTED_EDGE('',*,*,#1379,.F.);
#1398=DIRECTION('',(1.,0.,0.));
#1399=VECTOR('',#1398,1.);
#1400=CARTESIAN_POINT('',(0.,327.500000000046,-126.000000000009));
#1401=LINE('',#1400,#1399);
#1402=EDGE_CURVE('E628',#1319,#1369,#1401,.T.);
#1403=ORIENTED_EDGE('',*,*,#1402,.F.);
#1404=ORIENTED_EDGE('',*,*,#1320,.F.);
#1405=ORIENTED_EDGE('',*,*,#1297,.T.);
#1406=EDGE_LOOP('',(#1397,#1403,#1404,#1405));
#1407=FACE_BOUND('',#1406,.T.);
#1408=ADVANCED_FACE('F808',(#1407),#1396,.F.);
#1409=CARTESIAN_POINT('',(13.5000000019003,327.924624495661,-126.000000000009));
#1410=DIRECTION('',(-1.,0.,0.));
#1411=DIRECTION('',(0.,0.,-1.));
#1412=AXIS2_PLACEMENT_3D('',#1409,#1410,#1411);
#1413=PLANE('',#1412);
#1414=DIRECTION('',(0.,1.,0.));
#1415=VECTOR('',#1414,1.);
#1416=CARTESIAN_POINT('',(13.5000000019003,327.924624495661,-127.500000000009));
#1417=LINE('',#1416,#1415);
#1418=CARTESIAN_POINT('',(13.5000000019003,327.924624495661,-127.500000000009));
#1419=VERTEX_POINT('',#1418);
#1420=EDGE_CURVE('E621',#1327,#1419,#1417,.T.);
#1421=ORIENTED_EDGE('',*,*,#1420,.F.);
#1422=ORIENTED_EDGE('',*,*,#1328,.T.);
#1423=DIRECTION('',(0.,1.,0.));
#1424=VECTOR('',#1423,1.);
#1425=CARTESIAN_POINT('',(13.5000000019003,327.924624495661,-126.000000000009));
#1426=LINE('',#1425,#1424);
#1427=CARTESIAN_POINT('',(13.5000000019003,327.924624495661,-126.000000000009));
#1428=VERTEX_POINT('',#1427);
#1429=EDGE_CURVE('E591',#1319,#1428,#1426,.T.);
#1430=ORIENTED_EDGE('',*,*,#1429,.T.);
#1431=DIRECTION('',(0.,0.,-1.));
#1432=VECTOR('',#1431,1.);
#1433=CARTESIAN_POINT('',(13.5000000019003,327.924624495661,-126.000000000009));
#1434=LINE('',#1433,#1432);
#1435=EDGE_CURVE('E593',#1428,#1419,#1434,.T.);
#1436=ORIENTED_EDGE('',*,*,#1435,.T.);
#1437=EDGE_LOOP('',(#1421,#1422,#1430,#1436));
#1438=FACE_BOUND('',#1437,.T.);
#1439=ADVANCED_FACE('F812',(#1438),#1413,.T.);
#1440=CARTESIAN_POINT('',(598.512572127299,327.500000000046,-125.000000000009));
#1441=DIRECTION('',(-1.,0.,0.));
#1442=DIRECTION('',(0.,1.,0.));
#1443=AXIS2_PLACEMENT_3D('',#1440,#1441,#1442);
#1444=CYLINDRICAL_SURFACE('',#1443,2.5);
#1445=ORIENTED_EDGE('',*,*,#1387,.T.);
#1446=ORIENTED_EDGE('',*,*,#1350,.F.);
#1447=ORIENTED_EDGE('',*,*,#1335,.T.);
#1448=DIRECTION('',(1.,0.,0.));
#1449=VECTOR('',#1448,1.);
#1450=CARTESIAN_POINT('',(0.,327.500000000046,-127.500000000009));
#1451=LINE('',#1450,#1449);
#1452=EDGE_CURVE('E602',#1327,#1371,#1451,.T.);
#1453=ORIENTED_EDGE('',*,*,#1452,.T.);
#1454=EDGE_LOOP('',(#1445,#1446,#1447,#1453));
#1455=FACE_BOUND('',#1454,.T.);
#1456=ADVANCED_FACE('F816',(#1455),#1444,.T.);
#1457=CARTESIAN_POINT('',(403.5000000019,327.924624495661,-126.000000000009));
#1458=DIRECTION('',(1.,0.,0.));
#1459=DIRECTION('',(0.,0.,1.));
#1460=AXIS2_PLACEMENT_3D('',#1457,#1458,#1459);
#1461=PLANE('',#1460);
#1462=DIRECTION('',(0.,-1.,0.));
#1463=VECTOR('',#1462,1.);
#1464=CARTESIAN_POINT('',(403.5000000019,327.924624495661,-126.000000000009));
#1465=LINE('',#1464,#1463);
#1466=CARTESIAN_POINT('',(403.5000000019,327.924624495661,-126.000000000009));
#1467=VERTEX_POINT('',#1466);
#1468=EDGE_CURVE('E604',#1467,#1369,#1465,.T.);
#1469=ORIENTED_EDGE('',*,*,#1468,.T.);
#1470=ORIENTED_EDGE('',*,*,#1372,.T.);
#1471=DIRECTION('',(0.,-1.,0.));
#1472=VECTOR('',#1471,1.);
#1473=CARTESIAN_POINT('',(403.5000000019,327.924624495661,-127.500000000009));
#1474=LINE('',#1473,#1472);
#1475=CARTESIAN_POINT('',(403.5000000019,327.924624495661,-127.500000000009));
#1476=VERTEX_POINT('',#1475);
#1477=EDGE_CURVE('E618',#1476,#1371,#1474,.T.);
#1478=ORIENTED_EDGE('',*,*,#1477,.F.);
#1479=DIRECTION('',(0.,0.,-1.));
#1480=VECTOR('',#1479,1.);
#1481=CARTESIAN_POINT('',(403.5000000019,327.924624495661,-126.000000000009));
#1482=LINE('',#1481,#1480);
#1483=EDGE_CURVE('E626',#1467,#1476,#1482,.T.);
#1484=ORIENTED_EDGE('',*,*,#1483,.F.);
#1485=EDGE_LOOP('',(#1469,#1470,#1478,#1484));
#1486=FACE_BOUND('',#1485,.T.);
#1487=ADVANCED_FACE('F820',(#1486),#1461,.T.);
#1488=CARTESIAN_POINT('',(0.,340.2488935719,-127.500000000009));
#1489=DIRECTION('',(0.,0.,1.));
#1490=DIRECTION('',(0.,-1.,0.));
#1491=AXIS2_PLACEMENT_3D('',#1488,#1489,#1490);
#1492=PLANE('',#1491);
#1493=DIRECTION('',(-0.792180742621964,0.61028654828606,0.));
#1494=VECTOR('',#1493,1.);
#1495=CARTESIAN_POINT('',(1.07071068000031,337.5,-127.500000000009));
#1496=LINE('',#1495,#1494);
#1497=EDGE_CURVE('E610',#1419,#840,#1496,.T.);
#1498=ORIENTED_EDGE('',*,*,#1497,.T.);
#1499=ORIENTED_EDGE('',*,*,#904,.T.);
#1500=DIRECTION('',(-0.79218074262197,-0.610286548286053,0.));
#1501=VECTOR('',#1500,1.);
#1502=CARTESIAN_POINT('',(415.9292893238,337.5,-127.500000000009));
#1503=LINE('',#1502,#1501);
#1504=EDGE_CURVE('E615',#881,#1476,#1503,.T.);
#1505=ORIENTED_EDGE('',*,*,#1504,.T.);
#1506=ORIENTED_EDGE('',*,*,#1477,.T.);
#1507=ORIENTED_EDGE('',*,*,#1452,.F.);
#1508=ORIENTED_EDGE('',*,*,#1420,.T.);
#1509=EDGE_LOOP('',(#1498,#1499,#1505,#1506,#1507,#1508));
#1510=FACE_BOUND('',#1509,.T.);
#1511=ADVANCED_FACE('F824',(#1510),#1492,.F.);
#1512=CARTESIAN_POINT('',(415.9292893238,337.5,-126.000000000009));
#1513=DIRECTION('',(0.610286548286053,-0.79218074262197,0.));
#1514=DIRECTION('',(-0.79218074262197,-0.610286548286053,0.));
#1515=AXIS2_PLACEMENT_3D('',#1512,#1513,#1514);
#1516=PLANE('',#1515);
#1517=ORIENTED_EDGE('',*,*,#1504,.F.);
#1518=ORIENTED_EDGE('',*,*,#882,.F.);
#1519=DIRECTION('',(-0.79218074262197,-0.610286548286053,0.));
#1520=VECTOR('',#1519,1.);
#1521=CARTESIAN_POINT('',(415.9292893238,337.5,-126.000000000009));
#1522=LINE('',#1521,#1520);
#1523=EDGE_CURVE('E623',#873,#1467,#1522,.T.);
#1524=ORIENTED_EDGE('',*,*,#1523,.T.);
#1525=ORIENTED_EDGE('',*,*,#1483,.T.);
#1526=EDGE_LOOP('',(#1517,#1518,#1524,#1525));
#1527=FACE_BOUND('',#1526,.T.);
#1528=ADVANCED_FACE('F828',(#1527),#1516,.T.);
#1529=CARTESIAN_POINT('',(0.,340.2488935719,-126.000000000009));
#1530=DIRECTION('',(0.,0.,1.));
#1531=DIRECTION('',(0.,-1.,0.));
#1532=AXIS2_PLACEMENT_3D('',#1529,#1530,#1531);
#1533=PLANE('',#1532);
#1534=ORIENTED_EDGE('',*,*,#923,.F.);
#1535=DIRECTION('',(-0.792180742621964,0.61028654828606,0.));
#1536=VECTOR('',#1535,1.);
#1537=CARTESIAN_POINT('',(1.07071068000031,337.5,-126.000000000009));
#1538=LINE('',#1537,#1536);
#1539=EDGE_CURVE('E631',#1428,#838,#1538,.T.);
#1540=ORIENTED_EDGE('',*,*,#1539,.F.);
#1541=ORIENTED_EDGE('',*,*,#1429,.F.);
#1542=ORIENTED_EDGE('',*,*,#1402,.T.);
#1543=ORIENTED_EDGE('',*,*,#1468,.F.);
#1544=ORIENTED_EDGE('',*,*,#1523,.F.);
#1545=EDGE_LOOP('',(#1534,#1540,#1541,#1542,#1543,#1544));
#1546=FACE_BOUND('',#1545,.T.);
#1547=ADVANCED_FACE('F832',(#1546),#1533,.T.);
#1548=CARTESIAN_POINT('',(1.07071068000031,337.5,-126.000000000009));
#1549=DIRECTION('',(-0.610286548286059,-0.792180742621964,0.));
#1550=DIRECTION('',(-0.792180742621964,0.61028654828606,0.));
#1551=AXIS2_PLACEMENT_3D('',#1548,#1549,#1550);
#1552=PLANE('',#1551);
#1553=ORIENTED_EDGE('',*,*,#1497,.F.);
#1554=ORIENTED_EDGE('',*,*,#1435,.F.);
#1555=ORIENTED_EDGE('',*,*,#1539,.T.);
#1556=ORIENTED_EDGE('',*,*,#841,.T.);
#1557=EDGE_LOOP('',(#1553,#1554,#1555,#1556));
#1558=FACE_BOUND('',#1557,.T.);
#1559=ADVANCED_FACE('F738',(#1558),#1552,.T.);
#1560=CARTESIAN_POINT('',(0.,1.5,-127.501024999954));
#1561=DIRECTION('',(0.,1.,0.));
#1562=DIRECTION('',(0.,0.,1.));
#1563=AXIS2_PLACEMENT_3D('',#1560,#1561,#1562);
#1564=PLANE('',#1563);
#1565=ORIENTED_EDGE('',*,*,#804,.T.);
#1566=ORIENTED_EDGE('',*,*,#820,.T.);
#1567=ORIENTED_EDGE('',*,*,#745,.T.);
#1568=ORIENTED_EDGE('',*,*,#774,.F.);
#1569=EDGE_LOOP('',(#1565,#1566,#1567,#1568));
#1570=FACE_BOUND('',#1569,.T.);
#1571=ADVANCED_FACE('F271',(#1570),#1564,.F.);
#1572=CARTESIAN_POINT('',(268.5,340.,-30.));
#1573=DIRECTION('',(0.,1.,0.));
#1574=DIRECTION('',(0.,0.,1.));
#1575=AXIS2_PLACEMENT_3D('',#1572,#1573,#1574);
#1576=CYLINDRICAL_SURFACE('',#1575,5.09999999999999);
#1577=ORIENTED_EDGE('',*,*,#42,.T.);
#1578=EDGE_LOOP('',(#1577));
#1579=FACE_BOUND('',#1578,.T.);
#1580=ORIENTED_EDGE('',*,*,#116,.T.);
#1581=EDGE_LOOP('',(#1580));
#1582=FACE_BOUND('',#1581,.T.);
#1583=ADVANCED_FACE('F728',(#1579,#1582),#1576,.F.);
#1584=CARTESIAN_POINT('',(148.5,340.,-30.));
#1585=DIRECTION('',(0.,1.,0.));
#1586=DIRECTION('',(0.,0.,1.));
#1587=AXIS2_PLACEMENT_3D('',#1584,#1585,#1586);
#1588=CYLINDRICAL_SURFACE('',#1587,5.09999999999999);
#1589=ORIENTED_EDGE('',*,*,#31,.T.);
#1590=EDGE_LOOP('',(#1589));
#1591=FACE_BOUND('',#1590,.T.);
#1592=ORIENTED_EDGE('',*,*,#105,.T.);
#1593=EDGE_LOOP('',(#1592));
#1594=FACE_BOUND('',#1593,.T.);
#1595=ADVANCED_FACE('F650',(#1591,#1594),#1588,.F.);
#1596=CLOSED_SHELL('',(#92,#166,#206,#246,#268,#290,#312,#329,#346,#363,#396,#421,#446,#463,
#494,#518,#542,#559,#583,#607,#619,#631,#664,#697,#714,#731,#762,#786,#810,#827,#860,#893,#910,
#927,#967,#998,#1029,#1046,#1063,#1096,#1129,#1146,#1177,#1194,#1225,#1256,#1287,#1306,#1339,
#1358,#1391,#1408,#1439,#1456,#1487,#1511,#1528,#1547,#1559,#1571,#1583,#1595));
#1597=MANIFOLD_SOLID_BREP('B2',#1596);
#1598=ADVANCED_BREP_SHAPE_REPRESENTATION('',(#18,#1597),#14);
#1599=SHAPE_DEFINITION_REPRESENTATION(#9,#1598);
ENDSEC;
END-ISO-10303-21;
